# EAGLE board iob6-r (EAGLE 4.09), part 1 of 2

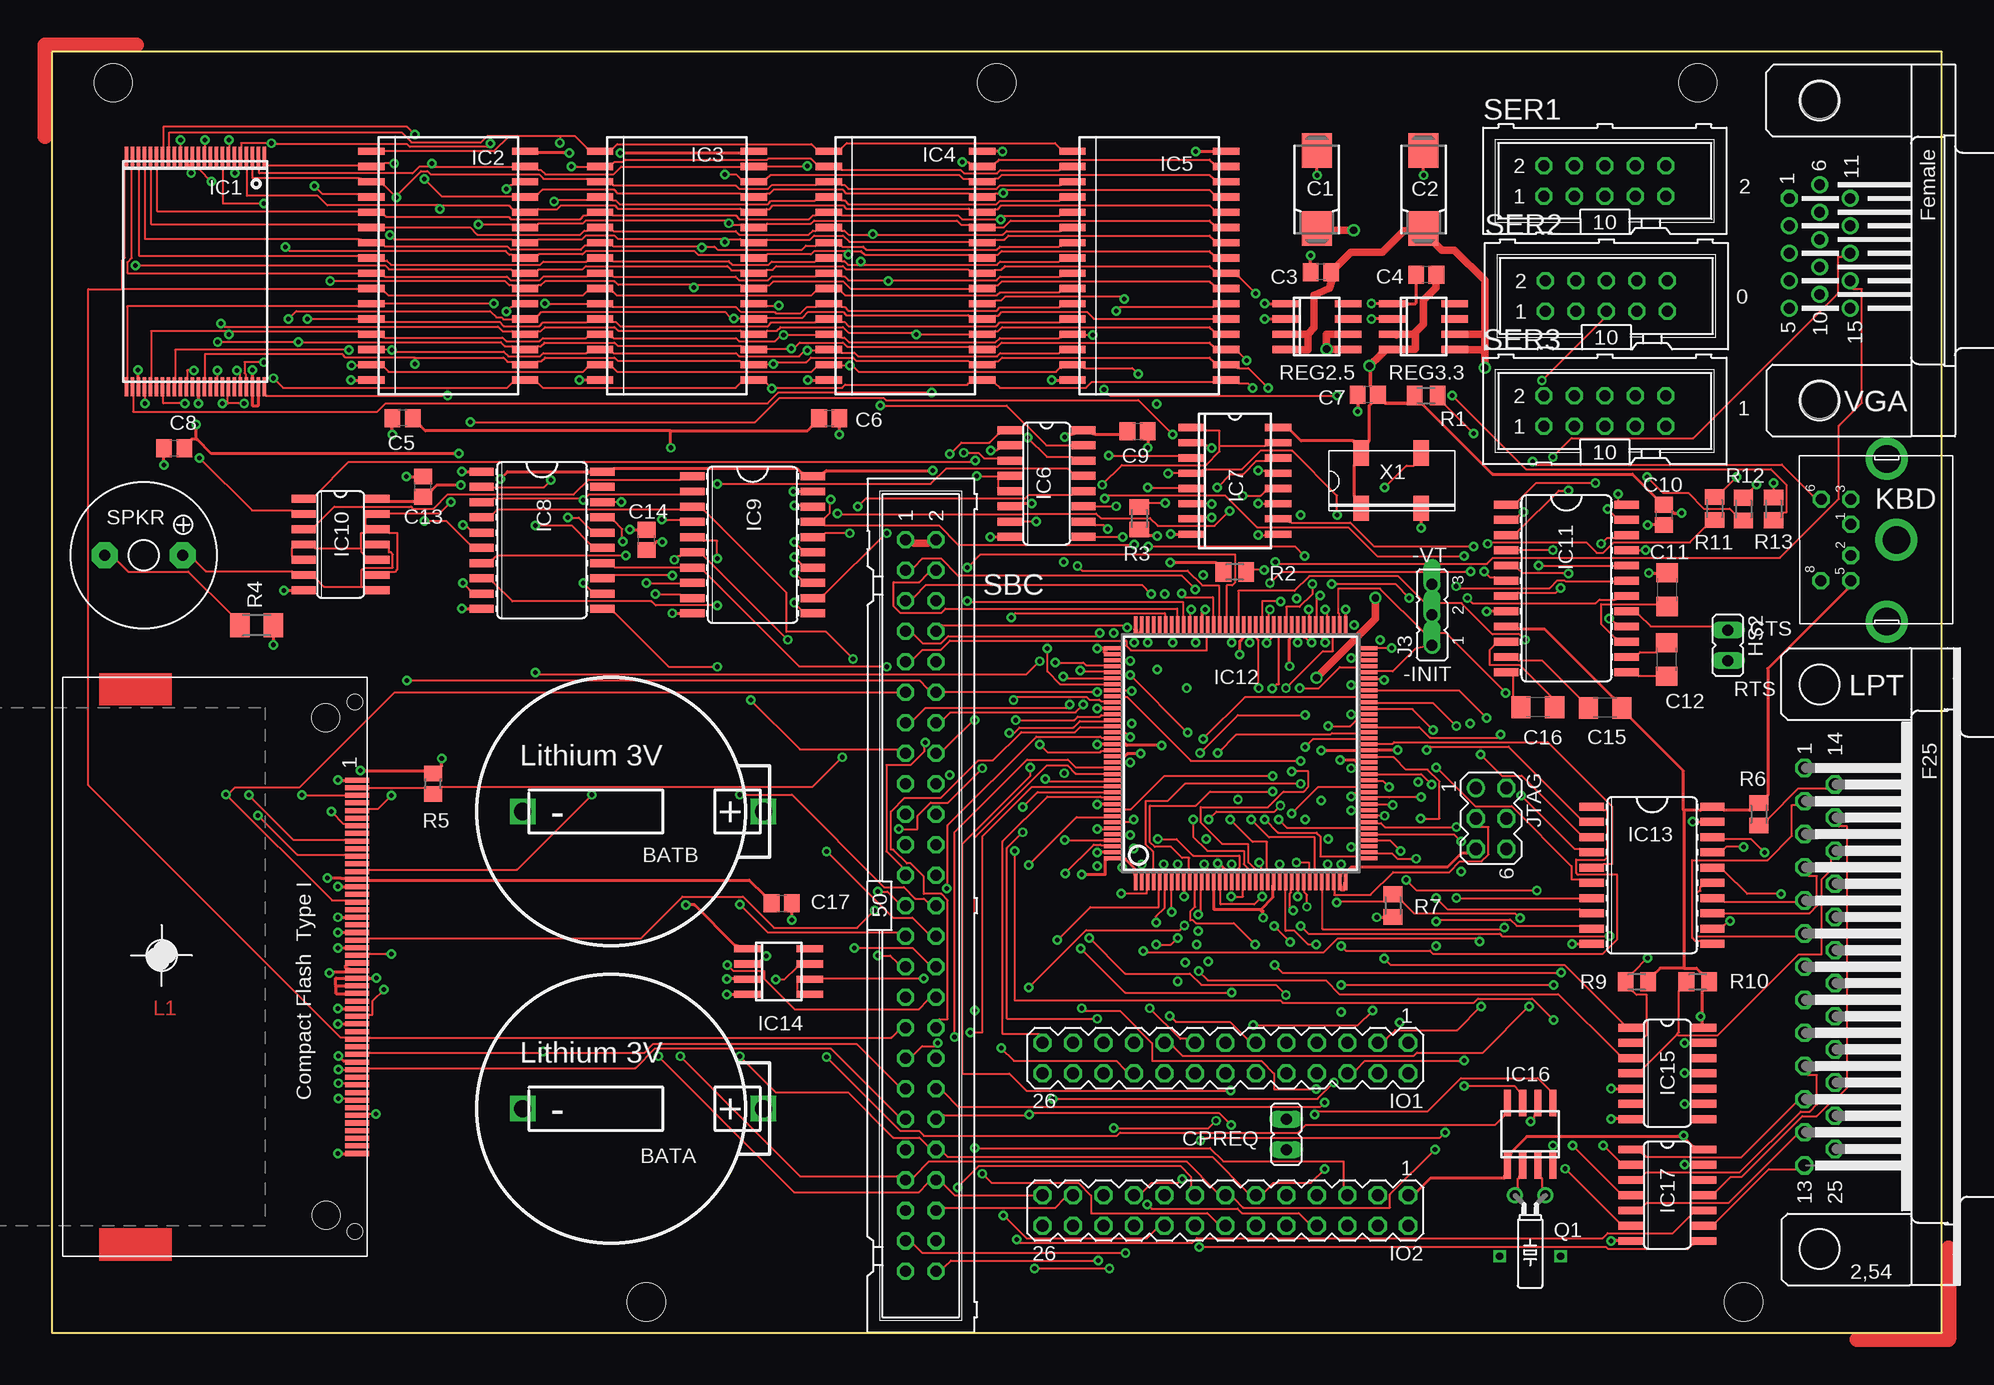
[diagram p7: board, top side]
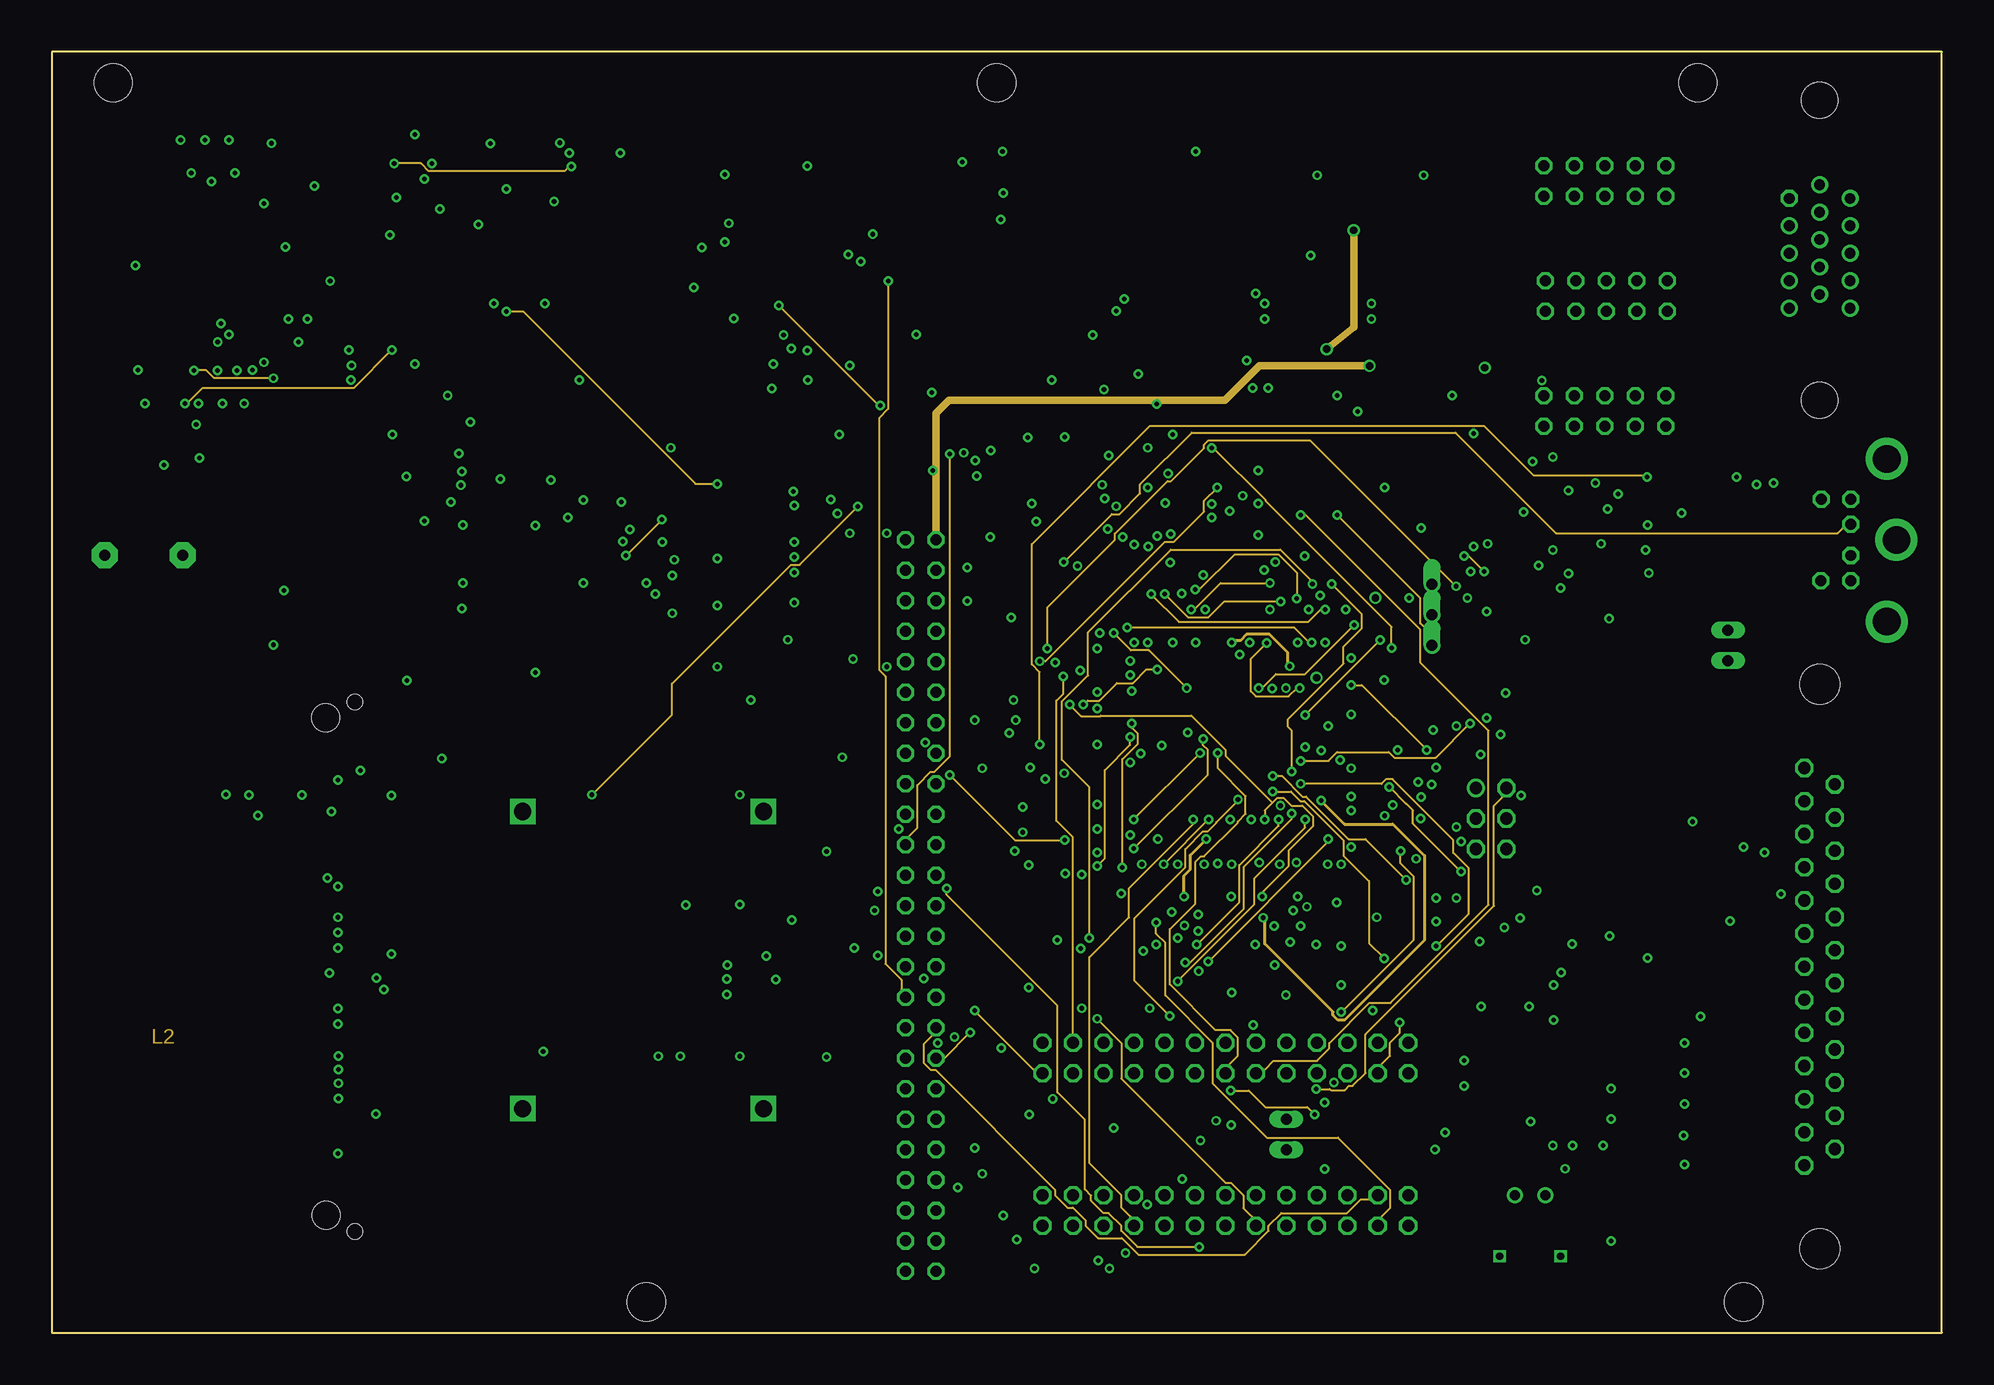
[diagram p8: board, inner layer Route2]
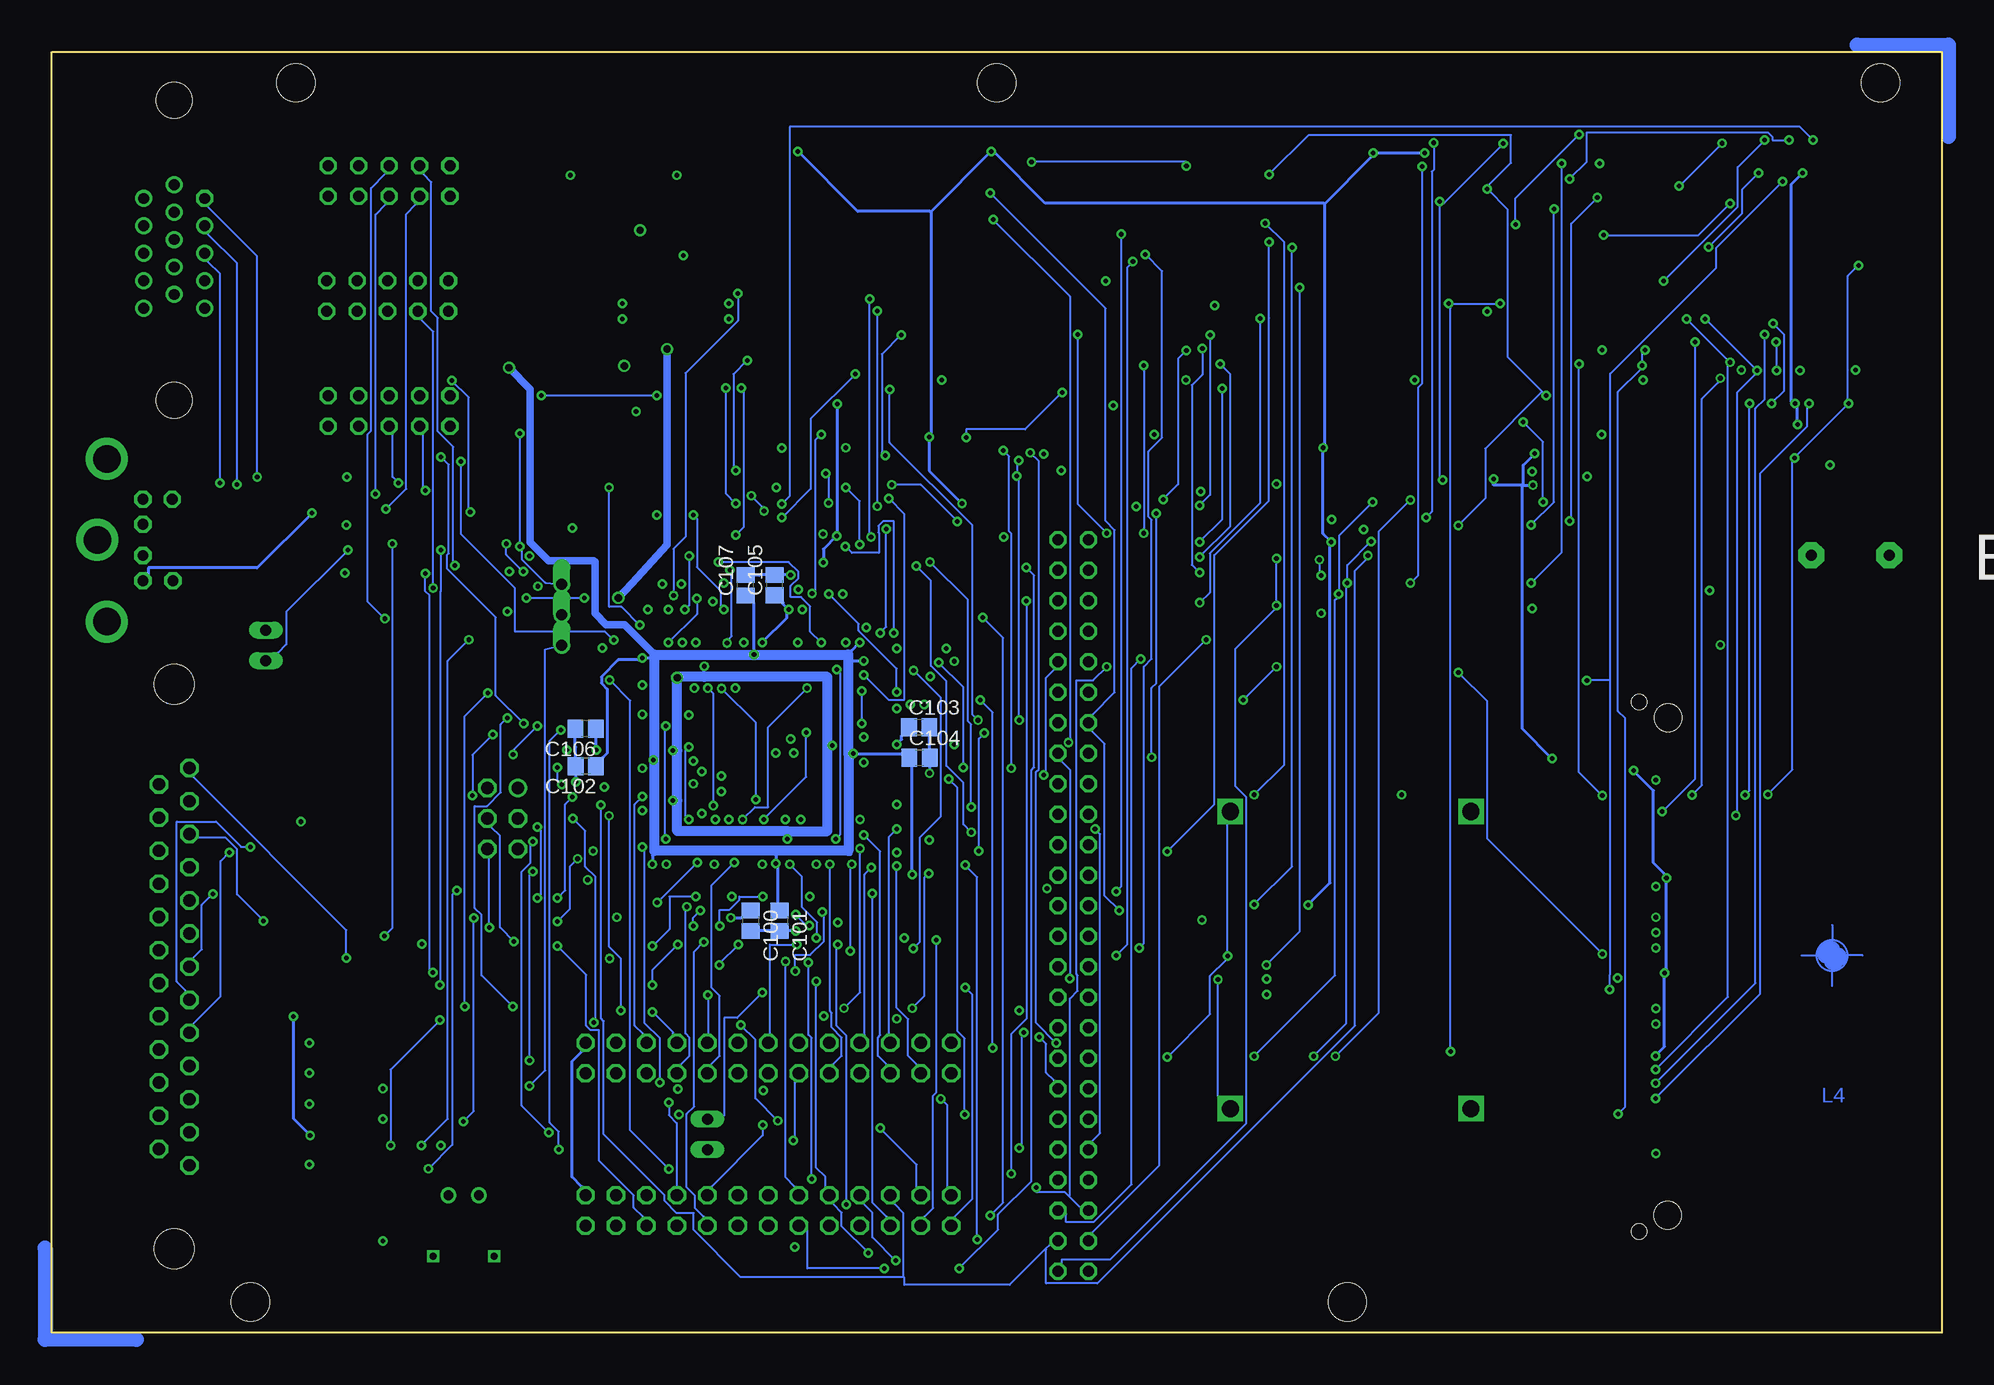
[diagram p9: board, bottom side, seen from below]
Size 157.53 x 106.73 mm. Coordinates in mm from the lower left corner, seen from the top.
Outline: 0,0 157.53,0 157.53,106.73 0,106.73 0,0
Copper layers used: Top, Route2, Bottom
Net classes: 1 power: width 0.254 mm, drill 0.203 mm, clearance 0.381 mm; 2 gnd: width 0.254 mm, clearance 0.381 mm; 3 power2: width 0.254 mm, clearance 0.381 mm
Holes 3.17 mm at 78.77,104.17 141,2.57 5.11,104.17 49.56,2.57 137.19,104.17

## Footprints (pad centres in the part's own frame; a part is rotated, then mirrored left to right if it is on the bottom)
CR2032HOLDER = drill 1.422 square: + 12.7,0; - -7.366,0
085CS_1AR = smd 2.9 x 2.5: + 3.25,0; - -3.25,0
C0805 = smd 1.3 x 1.5: 1 -0.85,0; 2 0.85,0
C1206 = smd 1.6 x 1.8: 1 -1.4,0; 2 1.4,0
CF_SOCKET2_SMT = smd 0.42 x 2: 1 15.545,-17.805; 2 14.275,-17.805; 3 13.005,-17.805; 4 11.735,-17.805; 5 10.465,-17.805; 6 9.195,-17.805; 7 7.925,-17.805; 8 6.655,-17.805; 9 5.385,-17.805; 10 4.115,-17.805; 11 2.845,-17.805; 12 1.575,-17.805; 13 0.305,-17.805; 14 -0.965,-17.805; 15 -2.235,-17.805; 16 -3.505,-17.805; 17 -4.775,-17.805; 18 -6.045,-17.805; 19 -7.315,-17.805; 20 -8.585,-17.805; 21 -9.855,-17.805; 22 -11.125,-17.805; 23 -12.395,-17.805; 24 -13.665,-17.805; 25 -14.935,-17.805; 26 14.91,-17.805; 27 13.64,-17.805; 28 12.37,-17.805; 29 11.1,-17.805; 30 9.83,-17.805; 31 8.56,-17.805; 32 7.29,-17.805; 33 6.02,-17.805; 34 4.75,-17.805; 35 3.48,-17.805; 36 2.21,-17.805; 37 0.94,-17.805; 38 -0.33,-17.805; 39 -1.6,-17.805; 40 -2.87,-17.805; 41 -4.14,-17.805; 42 -5.41,-17.805; 43 -6.68,-17.805; 44 -7.95,-17.805; 45 -9.22,-17.805; 46 -10.49,-17.805; 47 -11.76,-17.805; 48 -13.03,-17.805; 49 -14.3,-17.805; 50 -15.57,-17.805 | hole 2.3: 20.747,-15.177; -20.72,-15.208 | hole 1.27: -22.062,-17.6; 22.048,-17.6
JP1 = drill 0.914 long: 1 0,-1.27; 2 0,1.27
TSOP48 = smd 0.3 x 1.6: 1 -6.25,-9.1; 2 -5.75,-9.1; 3 -5.25,-9.1; 4 -4.75,-9.1; 5 -4.25,-9.1; 6 -3.75,-9.1; 7 -3.25,-9.1; 8 -2.75,-9.1; 9 -2.25,-9.1; 10 -1.75,-9.1; 11 -1.25,-9.1; 12 -0.75,-9.1; 13 -0.25,-9.1; 14 0.25,-9.1; 15 0.75,-9.1; 16 1.25,-9.1; 17 1.75,-9.1; 18 2.25,-9.1; 19 2.75,-9.1; 20 3.25,-9.1; 21 3.75,-9.1; 22 4.25,-9.1; 23 4.75,-9.1; 24 5.25,-9.1; 25 5.25,10.1; 26 4.75,10.1; 27 4.25,10.1; 28 3.75,10.1; 29 3.25,10.1; 30 2.75,10.1; 31 2.25,10.1; 32 1.75,10.1; 33 1.25,10.1; 34 0.75,10.1; 35 0.25,10.1; 36 -0.25,10.1; 37 -0.75,10.1; 38 -1.25,10.1; 39 -1.75,10.1; 40 -2.25,10.1; 41 -2.75,10.1; 42 -3.25,10.1; 43 -3.75,10.1; 44 -4.25,10.1; 45 -4.75,10.1; 46 -5.25,10.1; 47 -5.75,10.1; 48 -6.25,10.1
SOP32 = smd 0.6 x 2.2: 1 -9.525,-6.4; 2 -8.255,-6.4; 3 -6.985,-6.4; 4 -5.715,-6.4; 5 -4.445,-6.4; 6 -3.175,-6.4; 7 -1.905,-6.4; 8 -0.635,-6.4; 9 0.635,-6.4; 10 1.905,-6.4; 11 3.175,-6.4; 12 4.445,-6.4; 13 5.715,-6.4; 14 6.985,-6.4; 15 8.255,-6.4; 16 9.525,-6.4; 17 9.525,6.4; 18 8.255,6.4; 19 6.985,6.4; 20 5.715,6.4; 21 4.445,6.4; 22 3.175,6.4; 23 1.905,6.4; 24 0.635,6.4; 25 -0.635,6.4; 26 -1.905,6.4; 27 -3.175,6.4; 28 -4.445,6.4; 29 -5.715,6.4; 30 -6.985,6.4; 31 -8.255,6.4; 32 -9.525,6.4
SO16 = smd 0.66 x 2.032: 1 -4.445,-3.073; 2 -3.175,-3.073; 3 -1.905,-3.073; 4 -0.635,-3.073; 5 0.635,-3.073; 6 1.905,-3.073; 7 3.175,-3.073; 8 4.445,-3.073; 9 4.445,3.073; 10 3.175,3.073; 11 1.905,3.073; 12 0.635,3.073; 13 -0.635,3.073; 14 -1.905,3.073; 15 -3.175,3.073; 16 -4.445,3.073
SOP16 = smd 0.6 x 2.2: 1 -4.445,-3.6; 2 -3.175,-3.6; 3 -1.905,-3.6; 4 -0.635,-3.6; 5 0.635,-3.6; 6 1.905,-3.6; 7 3.175,-3.6; 8 4.445,-3.6; 9 4.445,3.6; 10 3.175,3.6; 11 1.905,3.6; 12 0.635,3.6; 13 -0.635,3.6; 14 -1.905,3.6; 15 -3.175,3.6; 16 -4.445,3.6
SO20W = smd 0.66 x 2.032: 1 -5.715,-5.029; 2 -4.445,-5.029; 3 -3.175,-5.029; 4 -1.905,-5.029; 5 -0.635,-5.029; 6 0.635,-5.029; 7 1.905,-5.029; 8 3.175,-5.029; 9 4.445,-5.029; 10 5.715,-5.029; 11 5.715,5.029; 12 4.445,5.029; 13 3.175,5.029; 14 1.905,5.029; 15 0.635,5.029; 16 -0.635,5.029; 17 -1.905,5.029; 18 -3.175,5.029; 19 -4.445,5.029; 20 -5.715,5.029
SO14 = smd 0.66 x 2.032: 1 -3.81,-3.073; 2 -2.54,-3.073; 3 -1.27,-3.073; 4 0,-3.073; 5 1.27,-3.073; 6 2.54,-3.073; 7 3.81,-3.073; 8 3.81,3.073; 9 2.54,3.073; 10 1.27,3.073; 11 0,3.073; 12 -1.27,3.073; 13 -2.54,3.073; 14 -3.81,3.073
SO24L = smd 0.66 x 2.032: 1 -6.985,-5.029; 2 -5.715,-5.029; 3 -4.445,-5.029; 4 -3.175,-5.029; 5 -1.905,-5.029; 6 -0.635,-5.029; 7 0.635,-5.029; 8 1.905,-5.029; 9 3.175,-5.029; 10 4.445,-5.029; 11 5.715,-5.029; 12 6.985,-5.029; 13 6.985,5.029; 14 5.715,5.029; 15 4.445,5.029; 16 3.175,5.029; 17 1.905,5.029; 18 0.635,5.029; 19 -0.635,5.029; 20 -1.905,5.029; 21 -3.175,5.029; 22 -4.445,5.029; 23 -5.715,5.029; 24 -6.985,5.029
TQFP144 = smd 0.3 x 1.6: 1 -8.75,-10.6; 2 -8.25,-10.6; 3 -7.75,-10.6; 4 -7.25,-10.6; 5 -6.75,-10.6; 6 -6.25,-10.6; 7 -5.75,-10.6; 8 -5.25,-10.6; 9 -4.75,-10.6; 10 -4.25,-10.6; 11 -3.75,-10.6; 12 -3.25,-10.6; 13 -2.75,-10.6; 14 -2.25,-10.6; 15 -1.75,-10.6; 16 -1.25,-10.6; 17 -0.75,-10.6; 18 -0.25,-10.6; 19 0.25,-10.6; 20 0.75,-10.6; 21 1.25,-10.6; 22 1.75,-10.6; 23 2.25,-10.6; 24 2.75,-10.6; 25 3.25,-10.6; 26 3.75,-10.6; 27 4.25,-10.6; 28 4.75,-10.6; 29 5.25,-10.6; 30 5.75,-10.6; 31 6.25,-10.6; 32 6.75,-10.6; 33 7.25,-10.6; 34 7.75,-10.6; 35 8.25,-10.6; 36 8.75,-10.6; 73 8.75,10.6; 74 8.25,10.6; 75 7.75,10.6; 76 7.25,10.6; 77 6.75,10.6; 78 6.25,10.6; 79 5.75,10.6; 80 5.25,10.6; 81 4.75,10.6; 82 4.25,10.6; 83 3.75,10.6; 84 3.25,10.6; 85 2.75,10.6; 86 2.25,10.6; 87 1.75,10.6; 88 1.25,10.6; 89 0.75,10.6; 90 0.25,10.6; 91 -0.25,10.6; 92 -0.75,10.6; 93 -1.25,10.6; 94 -1.75,10.6; 95 -2.25,10.6; 96 -2.75,10.6; 97 -3.25,10.6; 98 -3.75,10.6; 99 -4.25,10.6; 100 -4.75,10.6; 101 -5.25,10.6; 102 -5.75,10.6; 103 -6.25,10.6; 104 -6.75,10.6; 105 -7.25,10.6; 106 -7.75,10.6; 107 -8.25,10.6; 108 -8.75,10.6 | smd 1.6 x 0.3: 37 10.6,-8.75; 38 10.6,-8.25; 39 10.6,-7.75; 40 10.6,-7.25; 41 10.6,-6.75; 42 10.6,-6.25; 43 10.6,-5.75; 44 10.6,-5.25; 45 10.6,-4.75; 46 10.6,-4.25; 47 10.6,-3.75; 48 10.6,-3.25; 49 10.6,-2.75; 50 10.6,-2.25; 51 10.6,-1.75; 52 10.6,-1.25; 53 10.6,-0.75; 54 10.6,-0.25; 55 10.6,0.25; 56 10.6,0.75; 57 10.6,1.25; 58 10.6,1.75; 59 10.6,2.25; 60 10.6,2.75; 61 10.6,3.25; 62 10.6,3.75; 63 10.6,4.25; 64 10.6,4.75; 65 10.6,5.25; 66 10.6,5.75; 67 10.6,6.25; 68 10.6,6.75; 69 10.6,7.25; 70 10.6,7.75; 71 10.6,8.25; 72 10.6,8.75; 109 -10.6,8.75; 110 -10.6,8.25; 111 -10.6,7.75; 112 -10.6,7.25; 113 -10.6,6.75; 114 -10.6,6.25; 115 -10.6,5.75; 116 -10.6,5.25; 117 -10.6,4.75; 118 -10.6,4.25; 119 -10.6,3.75; 120 -10.6,3.25; 121 -10.6,2.75; 122 -10.6,2.25; 123 -10.6,1.75; 124 -10.6,1.25; 125 -10.6,0.75; 126 -10.6,0.25; 127 -10.6,-0.25; 128 -10.6,-0.75; 129 -10.6,-1.25; 130 -10.6,-1.75; 131 -10.6,-2.25; 132 -10.6,-2.75; 133 -10.6,-3.25; 134 -10.6,-3.75; 135 -10.6,-4.25; 136 -10.6,-4.75; 137 -10.6,-5.25; 138 -10.6,-5.75; 139 -10.6,-6.25; 140 -10.6,-6.75; 141 -10.6,-7.25; 142 -10.6,-7.75; 143 -10.6,-8.25; 144 -10.6,-8.75
SO08 = smd 0.6 x 2.2: 1 -1.905,-2.6; 2 -0.635,-2.6; 3 0.635,-2.6; 4 1.905,-2.6; 5 1.905,2.6; 6 0.635,2.6; 7 -0.635,2.6; 8 -1.905,2.6
MA13-2 = drill 1.016 octagon: 1 -15.24,-1.27; 2 -15.24,1.27; 3 -12.7,-1.27; 4 -12.7,1.27; 5 -10.16,-1.27; 6 -10.16,1.27; 7 -7.62,-1.27; 8 -7.62,1.27; 9 -5.08,-1.27; 10 -5.08,1.27; 11 -2.54,-1.27; 12 -2.54,1.27; 13 0,-1.27; 14 0,1.27; 15 2.54,-1.27; 16 2.54,1.27; 17 5.08,-1.27; 18 5.08,1.27; 19 7.62,-1.27; 20 7.62,1.27; 21 10.16,-1.27; 22 10.16,1.27; 23 12.7,-1.27; 24 12.7,1.27; 25 15.24,-1.27; 26 15.24,1.27
JP2 = drill 0.914 offset: 1 -2.54,0; 2 0,0; 3 2.54,0
MA03-2 = drill 1.016 round: 1 -2.54,-1.27 | drill 1.016 octagon: 2 -2.54,1.27; 3 0,-1.27; 4 0,1.27; 5 2.54,-1.27; 6 2.54,1.27
M_DIN6 = drill 0.9 pad 1.422 octagon: 1 -1.3,-3.75; 2 1.3,-3.75; 3 -3.4,-3.75; 5 3.4,-3.75; 6 -3.4,-6.2; 8 3.4,-6.25 | drill 2.3 pad 3.5 round: SH1 6.8,-0.75; SH2 0,0.05; SH3 -6.75,-0.75
F25H = drill 1.016 octagon: 1 -16.561,-1.27; 2 -13.792,-1.27; 3 -11.049,-1.27; 4 -8.28,-1.27; 5 -5.512,-1.27; 6 -2.769,-1.27; 7 0,-1.27; 8 2.769,-1.27; 9 5.512,-1.27; 10 8.28,-1.27; 11 11.049,-1.27; 12 13.792,-1.27; 13 16.561,-1.27; 14 -15.189,1.27; 15 -12.421,1.27; 16 -9.652,1.27; 17 -6.909,1.27; 18 -4.14,1.27; 19 -1.372,1.27; 20 1.372,1.27; 21 4.14,1.27; 22 6.909,1.27; 23 9.652,1.27; 24 12.421,1.27; 25 15.189,1.27 | hole 3.302: -23.52,0; 23.52,0
TC26H = drill 0.813 round: 1 -1.27,0; 2 1.27,0
M0805 = smd 1.3 x 1.6: 1 -0.95,0; 2 0.95,0
M1206 = smd 1.6 x 2: 1 -1.4,0; 2 1.4,0
R0805 = smd 1.3 x 1.5: 1 -0.85,0; 2 0.85,0
ML50 = drill 0.914 octagon: 1 -30.48,-1.27; 2 -30.48,1.27; 3 -27.94,-1.27; 4 -27.94,1.27; 5 -25.4,-1.27; 6 -25.4,1.27; 7 -22.86,-1.27; 8 -22.86,1.27; 9 -20.32,-1.27; 10 -20.32,1.27; 11 -17.78,-1.27; 12 -17.78,1.27; 13 -15.24,-1.27; 14 -15.24,1.27; 15 -12.7,-1.27; 16 -12.7,1.27; 17 -10.16,-1.27; 18 -10.16,1.27; 19 -7.62,-1.27; 20 -7.62,1.27; 21 -5.08,-1.27; 22 -5.08,1.27; 23 -2.54,-1.27; 24 -2.54,1.27; 25 0,-1.27; 26 0,1.27; 27 2.54,-1.27; 28 2.54,1.27; 29 5.08,-1.27; 30 5.08,1.27; 31 7.62,-1.27; 32 7.62,1.27; 33 10.16,-1.27; 34 10.16,1.27; 35 12.7,-1.27; 36 12.7,1.27; 37 15.24,-1.27; 38 15.24,1.27; 39 17.78,-1.27; 40 17.78,1.27; 41 20.32,-1.27; 42 20.32,1.27; 43 22.86,-1.27; 44 22.86,1.27; 45 25.4,-1.27; 46 25.4,1.27; 47 27.94,-1.27; 48 27.94,1.27; 49 30.48,-1.27; 50 30.48,1.27
ML10 = drill 0.914 octagon: 1 -5.08,-1.27; 2 -5.08,1.27; 3 -2.54,-1.27; 4 -2.54,1.27; 5 0,-1.27; 6 0,1.27; 7 2.54,-1.27; 8 2.54,1.27; 9 5.08,-1.27; 10 5.08,1.27
KSS1201 = drill 0.914 pad 2.159 octagon: + 3.251,0; - -3.251,0
HDF15H = drill 0.9 octagon: 1 4.329,2.54 | drill 0.9 round: 2 2.043,2.54; 3 -0.243,2.54; 4 -2.529,2.54; 5 -4.815,2.54; 6 5.472,0; 7 3.186,0; 8 0.9,0; 9 -1.386,0; 10 -3.672,0; 11 4.329,-2.54; 12 2.043,-2.54; 13 -0.243,-2.54; 14 -2.529,-2.54; 15 -4.815,-2.54 | hole 3: -12.5,0; 12.5,0
SG636 = smd 1.3 x 2.1: P$1 0,0; P$2 5,0; P$3 5,4.6; P$4 0,4.6

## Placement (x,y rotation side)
BATA  [CR2032HOLDER]  46.61,18.67 0 top
BATB  [CR2032HOLDER]  46.61,43.43 0 top
C1  10u  [085CS_1AR]  105.44,95.28 270 top
C2  10u  [085CS_1AR]  114.33,95.28 270 top
C3  0u1  [C0805]  105.77,88.39 180 top
C4  0u1  [C0805]  114.55,88.16 180 top
C5  0u1  [C0805]  29.24,76.23 180 top
C6  0u1  [C0805]  64.8,76.23 0 top
C7  0u1  [C0805]  109.68,78.16 180 top
C8  0u1  [C0805]  10.19,73.69 180 top
C9  0u1  [C0805]  90.5,75.13 0 top
C10  0u1  [C0805]  134.37,68.15 270 top
C11  [C1206]  134.65,61.93 90 top
C12  [C1206]  134.59,56.11 90 top
C13  0u1  [C0805]  30.94,70.51 90 top
C14  0u1  [C0805]  49.56,66.07 90 top
C15  [C1206]  129.46,52.07 180 top
C16  [C1206]  123.85,52.12 180 top
C17  0u1  [C0805]  60.83,35.79 0 top
C100  0u1  [C0805]  99.29,34.34 270 bottom
C101  0u1  [C0805]  96.88,34.34 270 bottom
C102  0u1  [C0805]  113.03,47.22 180 bottom
C103  0u1  [C0805]  85.24,50.47 0 bottom
C104  0u1  [C0805]  85.22,47.93 0 bottom
C105  0u1  [C0805]  97.28,62.31 90 bottom
C106  0u1  [C0805]  113.06,50.32 180 bottom
C107  0u1  [C0805]  99.72,62.28 90 bottom
CF1  CF_CMM_SOCKET2  [CF_SOCKET2_SMT]  7.65,30.51 90 top
CPREQ  [JP1]  102.9,16.54 0 top
HS2  [JP1]  139.7,57.28 180 top
IC1  LH28F400BVHE-BL  [TSOP48]  11.46,88.93 180 top
IC2  TC554001AF  [SOP32]  33.05,88.93 270 top
IC3  TC554001AF  [SOP32]  52.1,88.93 270 top
IC4  TC554001AF  [SOP32]  71.15,88.93 270 top
IC5  TC554001AF  [SOP32]  91.47,88.93 270 top
IC6  74ACT138D  [SO16]  82.91,70.76 270 top
IC7  74HC367E  [SOP16]  98.6,70.99 270 top
IC8  74ACT373D  [SO20W]  40.84,66.04 270 top
IC9  74ACT245DW  [SO20W]  58.39,65.66 270 top
IC10  74ACT32D  [SO14]  24.05,65.68 270 top
IC11  MAX208ECWG  [SO24L]  126.24,62.03 270 top
IC12  [TQFP144]  99.09,48.29 0 top
IC13  74ACT245DW  [SO20W]  133.38,38.13 270 top
IC14  [SO08]  60.58,30.1 270 top
IC15  74ACT05D  [SO14]  134.65,21.62 270 top
IC16  DS1302  [SO08]  123.22,16.54 0 top
IC17  74ACT04D  [SO14]  134.65,11.46 270 top
IO1  [MA13-2]  97.82,22.89 180 top
IO2  [MA13-2]  97.82,10.19 180 top
J3  [JP2]  115.04,59.82 90 top
JTAG  [MA03-2]  119.96,42.85 270 top
KBD  [M_DIN6]  153.7,66.07 270 top
LPT  [F25H]  147.35,30.51 270 top
Q1  32768  [TC26H]  123.22,11.46 180 top
R1  10K  [M0805]  114.55,78.11 180 top
R2  10K  [M0805]  98.6,63.4 0 top
R3  10K  [M0805]  90.63,67.87 90 top
R4  100  [M1206]  17.07,58.95 0 top
R5  10K  [R0805]  31.78,45.75 90 top
R6  4K7  [M0805]  142.27,43.21 90 top
R7  10K  [M0805]  111.79,35.59 90 top
R9  4K7  [M0805]  132.11,29.24 0 top
R10  4K7  [M0805]  137.19,29.24 0 top
R11  68  [M0805]  138.58,68.68 90 top
R12  68  [M0805]  141,68.63 90 top
R13  68  [M0805]  143.51,68.66 90 top
REG2.5  TPS77725D  [SO08]  105.44,83.85 270 top
REG3.3  TPS77733D  [SO08]  114.33,83.85 270 top
SBC  ML50E  [ML50]  72.42,35.59 270 top
SER1  [ML10]  129.44,95.99 0 top
SER2  [ML10]  129.57,86.39 0 top
SER3  [ML10]  129.44,76.81 0 top
SPKR  KSS1201  [KSS1201]  7.65,64.8 0 top
U$34  [PASS-ROUND]  9.14,31.45 0 top
U$42  [ANGLE-ARROW-NW1-16]  0.08,106.65 0 top
U$43  [ANGLE-ARROW-SE1-16]  157.45,0.08 0 top
VGA  [HDF15H]  147.35,90.2 90 top
X1  29.4912MHz  [SG636]  109.14,68.71 0 top

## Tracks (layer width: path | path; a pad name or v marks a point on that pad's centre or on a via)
2V5  (via drill 0.38, 0.61)
  Top 0.254: 100.76,35.27 96.88,35.27 96.88,36.91 IC12.14 | 100.76,35.27 101.79,36.3 101.79,36.91 IC12.24 | v100.95,34.58 100.95,35.15 100.8,35.15 100.76,35.27 | v96.11,60.26 95.85,60.26 95.85,59.65 IC12.97 | v98.32,57.52 98.32,58.09 IC12.92 | v112.15,48.56 110.48,48.56 IC12.55 108.92,48.53 v105.79,48.53 | v87.12,49.02 87.69,49.02 IC12.125 89.26,49.02 89.52,49.02 89.6,48.95 v92.49,48.95 | v94.36,36.33 94.36,36.91 IC12.9 | v103.16,55.54 103.16,57.79 103.31,57.94 103.31,58.09 IC12.82
  Top 0.61: v106.25,81.97 106.22,81.94 | v110.31,61.24 110.31,59.49 v105.41,54.58 | 106.22,81.94 REG2.5.5 | 106.22,81.94 106.22,83.21 REG2.5.6 | C1.+ 105.59,91.87 v108.51,91.87
  Route2 0.254: v94.36,36.33 94.36,38.09 94.89,38.62 94.89,39.8 v96.23,41.14 | v98.32,57.52 98.67,57.67 99.05,57.67 99.58,58.2 101.49,58.2 103.01,56.68 103.01,55.88 v103.16,55.54 | v105.79,44.34 107.73,42.39 111.77,42.39 114.4,39.76 114.4,32.72 107.73,26.05 107.2,26.05 106.78,26.47 106.78,26.73 101.1,32.41 101.1,34.24 v100.95,34.58
  Route2 0.61: v108.51,91.87 108.51,83.77 106.22,81.94 v106.25,81.97
  Bottom 0.254: v100.95,34.58 100.04,34.58 C100.1 | C105.1 96.57,60.83 96.57,60.72 v96.11,60.26 96.27,59.92 96.27,59.58 v98.32,57.52 | v112.15,48.56 112.15,49.59 C106.1 | v87.12,49.02 86.7,49.44 86.7,49.75 C103.1 | v96.23,41.14 96.23,41.81 | 103.16,54.66 v103.16,55.54 | 92.89,48.95 v92.49,48.95 | 105.41,48.53 v105.79,48.53 | 105.41,44.34 v105.79,44.34
  Bottom 0.61: v106.25,81.97 106.25,65.66 108.74,62.92 109.19,62.41 v110.31,61.24
  Bottom 0.813: v105.41,54.58 105.41,48.53 105.41,44.34 105.41,41.81 96.23,41.81 92.89,41.81 92.89,48.95 92.89,54.66 103.16,54.66 105.54,54.66
5V  (via drill 0.38, 0.61)
  Top 0.254: v23.88,23.08 24.33,22.62 24.49,22.62 CF1.44 | v23.11,29.97 23.23,30.09 24.49,30.09 CF1.38 24.49,30.35 24.49,30.62 CF1.13 | v22.96,37.9 24.1,37.9 24.14,37.86 24.49,37.86 CF1.32 26.43,37.71 58.13,37.71 59.35,36.49 C17.1 | v25.7,46.85 31.04,46.85 R5.2 32.49,47.23 v32.49,47.84 | 11.57,97.26 11.34,97.26 IC1.14 | 11.57,97.26 IC1.13 | v12.22,77.44 12.22,78.05 IC1.37 | 12.03,74.43 v12.03,75.69 | 12.03,74.43 11.65,74.43 C8.1 | v11.61,96.65 11.61,97.14 11.57,97.26 | IC10.14 28.11,69.25 30.2,69.25 C13.1 31.69,70.24 32.07,70.62 v34.09,70.62 | v37.36,71.16 37.97,71.77 44.87,71.77 IC8.20 46.85,72.03 62.09,72.03 62.43,71.69 IC9.20 64.41,71.69 64.57,71.84 v73.41,71.84 | v33.93,73.25 13.28,73.25 12.14,74.4 12.03,74.43 | IC7.16 103.28,75.16 104.11,74.32 108.5,74.32 X1.P$4 | X1.P$1 108.53,69.75 108.53,72.26 X1.P$4 | v92.11,66.4 91.39,66.4 R3.1 | v93.22,64.19 97.03,64.19 R2.1 | 109.91,78.89 C7.1 | v109.83,80.57 109.91,80.11 | REG3.3.4 110.63,81.67 110.79,81.51 | REG3.3.3 112.08,82.93 112.19,83.21 | X1.P$4 109.79,74.32 109.79,77.25 109.94,77.41 C7.1 | 112.99,77.44 R1.2 114.25,77.37 120.08,71.54 131.74,71.54 133.64,69.63 C10.1 135.09,68.38 135.17,68.3 v135.85,68.3 | C7.1 111.16,77.44 | 135.97,16.33 136.73,15.57 IC17.14 | 135.97,16.33 122.94,16.33 121.6,15 IC16.1 121.03,12.87 114.9,12.87 113.79,11.76 IO2.1 | IC11.9 122.21,58.62 124.42,58.62 130.1,52.95 C15.1 131.62,51.19 136,46.81 136,43.65 136.04,43.54 | 137.53,26.35 137.53,28.45 R10.2 137.49,29.97 137.07,30.39 136.04,30.39 | 137.53,26.35 137.53,25.74 IC15.14 | 136.04,30.39 134.06,30.39 133.68,30.01 R9.2 | KBD.5 149.64,61.98 143.01,55.35 143.01,44.79 R6.2 141.49,43.54 139.4,43.54 IC13.20 137.41,43.54 136.04,43.54
  Top 0.254: 136.04,43.54 136.04,30.39 | v136,16.45 135.97,16.33 | 137.53,26.35 v137.41,26.35
  Top 0.305: 109.91,80.11 109.91,78.89 | 111.16,77.44 112.99,77.44
  Top 0.61: v109.83,80.57 110.79,81.51 111.23,81.94 REG3.3.4 113.59,81.94 113.64,81.99 113.64,83.21 | 113.64,83.21 112.19,83.21 | C4.1 115.34,88.1 115.34,87.07 114.33,86.06 114.33,84.05 113.51,83.24 113.51,83.19 113.61,83.19 113.64,83.21 | SBC.1 71.84,65.79 72.99,65.79 SBC.2
  Route2 0.254: 92.08,77.7 v92.08,77.41 | v73.41,71.84 73.69,71.84
  Route2 0.61: SBC.2 73.69,71.84 73.69,76.61 74.78,77.7 92.08,77.7 97.79,77.7 100.63,80.57 v109.83,80.57
  Bottom 0.254: v23.88,23.08 23.11,23.84 v23.11,29.97 22.96,30.32 v22.96,37.9 23.11,38.24 24.03,39.15 24.03,45.17 v25.7,46.85 | v12.03,75.69 12.03,77.25 v12.22,77.44 12.56,77.6 12.56,95.69 v11.61,96.65 | 34.96,70.62 37.36,70.62 v37.36,71.16 | 34.96,70.62 34.89,70.62 | 34.89,70.62 v34.09,70.62 | v33.93,73.25 34.89,72.3 34.89,70.62 | v32.49,47.84 34.96,50.32 34.96,70.62 | v93.22,64.19 93.22,65.29 v92.11,66.4 92.08,66.74 v92.08,77.41 | IO1.1 113.37,23.42 114.17,22.62 114.17,12.98 113.37,12.18 IO2.1 | v136,16.45 137.41,17.86 v137.41,26.35 | v135.85,68.3 140.42,63.73 149.49,63.73 149.49,63.2 KBD.5
B0  (via drill 0.38)
  Top 0.178: v80.34,51.04 85.22,51.04 85.52,51.35 87.35,51.35 87.46,51.46 87.69,51.46 IC12.120 | v87.69,78.59 88.19,78.09 v107.12,78.09 | v116.73,78.09 122.86,71.96 143.28,71.96 144.58,70.66 144.58,68.34 144.27,68.34 R13.1
  Bottom 0.178: v80.34,51.04 80.8,51.5 80.8,67.27 87.69,74.17 v87.69,78.59 | v107.12,78.09 v116.73,78.09
C0_L  (via drill 0.38)
  Top 0.178: v104.76,60.26 104.76,59.65 IC12.79 | v104.42,64.72 103.62,65.52 v91.39,65.52 | v87.35,58.32 87.08,58.05 74.7,58.05 74.09,57.44 72.57,57.44 71.84,58.17 SBC.7
  Bottom 0.178: v104.76,60.26 104.42,60.6 v104.42,64.72 | v91.39,65.52 90.86,64.99 88.61,64.99 88.61,66.66 88.65,66.7 88.65,67.23 88.27,67.61 87.35,67.61 v87.35,58.32
C1_L  (via drill 0.38)
  Top 0.178: v104.99,57.52 104.88,57.52 104.5,57.9 104.38,57.9 104.38,58.09 IC12.80 | v89.64,58.78 89.45,58.97 74.17,58.97 SBC.8
  Route2 0.178: v104.99,57.52 104.76,57.52 103.51,58.78 v89.64,58.78
CF_DETECT_L  (via drill 0.38)
  Top 0.178: CF1.26 26.43,45.4 31.04,45.4 R5.1 32.52,45.48 63.39,45.48 v65.86,47.96 | v99.24,69.75 100.76,69.75 101.1,70.09 IC7.12 | v98.17,68.49 96.91,67.23 92.19,67.23 91.54,67.88 87.43,67.88 87.05,68.26 81.03,68.26 80.95,68.19 65.56,68.19 v65.48,68.26
  Bottom 0.178: v99.24,69.75 98.17,68.68 v98.17,68.49 | v65.48,68.26 65.48,54.13 65.86,53.75 v65.86,47.96
CF_L  (via drill 0.38)
  Top 0.178: v45.02,44.83 38.77,38.58 26.43,38.58 CF1.7 | v67.16,68.83 67.84,69.52 81.14,69.52 81.45,69.82 84.99,69.82 IC6.12
  Route2 0.178: v45.02,44.83 51.69,51.5 51.69,54.09 61.6,64 62.32,64 v67.16,68.83
CF_READY  (via drill 0.38)
  Top 0.178: v28.3,31.57 26.43,31.57 CF1.37 | v40.3,55 40.45,54.85 81.22,54.85 v82.32,55.96 | v97.14,70.43 98.25,71.54 99.31,71.54 100.42,72.64 101.1,72.64 IC7.14
  Route2 0.178: v82.32,55.96 82.82,55.96 92.76,65.9 93.52,65.9 96.04,68.41 96.04,69.33 v97.14,70.43
  Bottom 0.178: v28.3,31.57 37.9,41.17 37.9,52.6 v40.3,55
CPUDX0
  Top 0.178: IC12.122 87.69,50.47 85.71,50.47 85.29,50.05 80.8,50.05 78.44,47.69 77.22,47.69 74.09,44.56 71.08,44.56 69.94,43.42 69.94,40.26 70.13,40.26 71.27,39.12 71.58,39.12 72.68,38.01 72.68,36.56 74.13,36.56 74.66,36.03 74.66,26.12 73.98,26.12 SBC.34
  Route2 0.178: IO2.3 109.79,11.11 109.11,11.11 107.96,9.97 102.48,9.97 101.41,8.9 101.41,8.48 99.43,6.5 90.55,6.5 89.18,7.87 87.2,7.87 86.17,8.9 86.17,9.36 85.1,10.43 84.65,10.43 83.62,11.46 83.62,11.91 73.63,21.89 73.25,21.89 72.68,22.47 72.68,24.07 73.37,24.75 SBC.34
CPUDX1  (via drill 0.38)
  Top 0.178: v76.53,25.02 77.56,25.02 77.56,41.36 81.67,45.48 87.69,45.48 IC12.132 | v76.91,15.38 96.53,15.38 97.64,14.27 107.66,14.27 107.66,12.18 IO2.5
  Route2 0.178: v76.53,25.02 74.36,22.85 SBC.36
  Bottom 0.178: v76.91,15.38 76.68,15.61 76.68,24.68 v76.53,25.02
CPUDX2  (via drill 0.38)
  Top 0.178: v75.23,24.64 75.23,41.71 81.29,47.76 84.68,47.76 85.33,47.12 87.69,47.12 IC12.129 | v106.1,19.19 105.75,18.85 75.54,18.85 74.36,20.03 SBC.38
  Bottom 0.178: v75.23,24.64 74.66,24.07 74.66,21.67 74.02,21.02 SBC.38 | v106.1,19.19 106.1,18.12 105.45,17.48 105.45,12.18 IO2.7
CPUDX3  (via drill 0.38)
  Top 0.178: v82.78,46.13 82.93,45.97 87.69,45.97 IC12.131 | SBC.40 74.36,18.12 81.37,18.12 v81.45,18.2 81.79,18.31 97.29,18.31 v98.29,17.32
  Bottom 0.178: v82.78,46.13 82.05,45.4 82.05,25.13 81.45,24.52 v81.45,18.2 | v98.29,17.32 98.29,16.45 102.55,12.18 IO2.9
CPUDX4  (via drill 0.38)
  Top 0.178: v50.28,61.56 50.32,61.52 52.37,61.52 IC9.9 | v47.46,69.22 IC8.18 | v111.05,54.39 110.97,54.47 110.48,54.47 IC12.67 | v106.1,13.63 104.95,12.48 101.83,12.48 101.1,11.76 IO2.11 99.62,11.76 96.72,14.66 74.66,14.66 74.36,14.96 SBC.42 72.99,15.57 72.3,16.26 70.13,16.26 66.36,20.03 60.34,20.03 v57.33,23.04
  Bottom 0.178: v47.46,69.22 50.2,66.47 50.2,61.63 v50.28,61.56 50.43,61.21 50.58,61.06 50.58,29.78 v57.33,23.04 | v111.05,54.39 109.33,52.68 109.33,16.87 v106.1,13.63
CPUDX5  (via drill 0.38)
  Top 0.178: v47.57,65.94 47.54,65.94 47.54,66.97 46.85,67.65 IC8.17 | v49.56,62.47 52.37,62.47 IC9.8 | v115.13,50.24 113.41,51.96 110.48,51.96 IC12.62 | v115.28,15.27 111.54,11.53 111.54,10.43 99.28,10.43 98.55,11.15 IO2.13 97.07,11.76 94.55,14.27 73.1,14.27 71.84,13.02 SBC.43 70.47,13.06 62.36,13.06 v52.37,23.04
  Bottom 0.178: v47.57,65.94 49.56,63.96 v49.56,62.47 49.63,62.13 49.63,25.78 v52.37,23.04 | v115.13,50.24 116.04,49.33 116.04,17.51 115.28,16.75 v115.28,15.27
CPUDX6  (via drill 0.38)
  Top 0.178: IC8.14 46.85,63.84 46.93,63.77 52.37,63.77 IC9.7 54.36,63.46 62.32,55.5 v69.6,55.5 | v106.36,50.55 108.23,50.55 108.65,50.97 108.92,50.97 IC12.60 | v75.5,12.1 77.29,13.89 94.06,13.89 94.93,13.02 94.93,12.18 IO2.15
  Route2 0.178: v106.36,41.14 106.36,40.91 v96.38,30.92
  Bottom 0.178: v106.36,50.55 106.44,50.47 106.44,41.21 v106.36,41.14 | v96.38,30.92 96.38,12.94 95.62,12.18 IO2.15 | 72.74,11.36 73.1,11.72 75.5,11.72 v75.5,12.1 | 72.74,11.36 71.84,10.46 SBC.45 | v69.6,55.5 70.74,54.36 72.15,54.36 72.15,29.9 72.03,29.78 72.03,28.49 72.68,27.84 72.68,11.42 72.74,11.36
CPUDX7  (via drill 0.38)
  Top 0.178: v51.73,63.12 46.85,63.12 IC8.13 | v51.88,64.41 52.18,64.72 52.37,64.72 IC9.6 54.36,64.72 v61.33,57.75 | v104.46,48.79 105.14,49.48 108.92,49.48 IC12.57 | v89.48,6.65 72.53,6.65 71.84,7.34 SBC.47
  Route2 0.178: v104.46,42.77 104.46,42.09 100.23,37.86 100.23,35.69 v93.83,29.29
  Bottom 0.178: v51.73,63.12 51.88,63.27 v51.88,64.41 | v104.46,48.79 104.72,48.53 104.72,43.04 v104.46,42.77 | v93.83,29.29 93.83,13.74 93.07,12.98 93.07,12.18 IO2.17 92.42,10.73 91.69,10.01 91.69,8.86 v89.48,6.65 | v61.33,57.75 65.21,53.86 65.21,13.97 70.85,8.33 SBC.47
CPUDX8  (via drill 0.38)
  Top 0.178: v55.46,60.6 50.32,60.6 49.97,60.95 38.39,60.95 36.79,62.55 IC8.8 | v55.46,64.53 55.46,65.98 54.36,65.98 IC9.5 | v103.35,43.27 105.56,45.48 108.92,45.48 IC12.49 | v94.21,12.83 93.87,12.48 91.66,12.48 90.93,11.76 IO2.19 | v87.2,6.01 74.93,6.01 74.36,5.44 SBC.50
  Route2 0.178: v103.35,43.27 103.35,42.81 99.35,38.81 99.35,35.34 94.86,30.85 v94.48,30.85
  Bottom 0.178: v55.46,64.53 v55.46,60.6 55.61,60.26 58.89,56.98 58.89,45.55 57.98,44.64 57.98,17.44 69.33,6.08 73.37,6.08 73.37,5.78 SBC.50 | v94.48,30.85 94.48,24.83 94.21,24.56 v94.21,12.83 | v87.2,6.01 89.14,7.95 89.14,10.01 89.87,10.73 IO2.19
CPUDX9  (via drill 0.38)
  Top 0.178: v47.84,64.76 37.1,64.76 36.79,64.45 IC8.7 | v50.85,67.77 52.37,67.77 IC9.4 | v111.77,43.99 110.48,43.99 IC12.46
  Route2 0.178: v47.84,64.76 v50.85,67.77
  Bottom 0.178: v111.77,43.99 111.77,26.2 111.54,25.97 111.54,16.52 106.48,11.46 106.48,11 105.45,9.97 104.04,9.97 104.04,8.56 100.11,4.64 86.55,4.64 | 86.55,4.64 86.55,9.97 87.31,10.73 IO2.21 | 74.72,6.98 77.71,3.99 86.47,3.99 86.47,4.6 86.55,4.64 | 74.72,6.98 74.36,7.34 SBC.48 | v47.84,64.76 47.99,64.41 48.91,63.5 48.91,25.59 70.4,4.1 74.66,4.1 74.66,6.92 74.72,6.98
CPUDX10  (via drill 0.38)
  Top 0.178: IC8.4 36.79,68.26 37.1,68.57 52.37,68.57 IC9.3 54.36,68.53 61.21,61.67 61.21,58.39 64.53,58.39 v66.78,56.15 | v111.09,43.08 110.48,43.08 IC12.44 | v110.1,26.85 108.88,25.63 v100.11,25.63 | v97.03,17.67 96.42,17.06 v88.49,17.06 | SBC.46 74.36,10.43 83.65,10.43 84.38,11.15 IO2.23
  Bottom 0.178: v111.09,43.08 111.09,32.14 110.1,31.15 v110.1,26.85 | v100.11,25.63 98.9,24.41 98.9,19.53 v97.03,17.67 | v88.49,17.06 85.45,14.01 85.45,12.18 IO2.23 | v66.78,56.15 67.54,55.38 67.54,12.37 70.7,9.21 72.99,9.21 72.99,9.89 SBC.46
CPUDX11  (via drill 0.38)
  Top 0.178: 44.3,69.48 44.41,69.48 44.79,69.86 52.37,69.86 IC9.2 | 44.3,69.48 36.79,69.48 IC8.3 | v108.31,40.49 108.92,40.49 IC12.39 | v106.86,20.87 105.49,19.49 v83.43,19.49 | IO2.25 75.23,11.46 74.32,12.37 SBC.44 72.99,12.45 72.26,11.72 61.86,11.72 v50.55,23.04 | v44.3,69.41 44.3,69.48
  Bottom 0.178: v108.31,40.49 108.12,40.3 108.12,25.78 106.86,24.52 v106.86,20.87 | v83.43,19.49 82.89,18.96 82.89,12.18 IO2.25 | v44.3,69.41 46.93,66.78 46.93,26.66 v50.55,23.04
CTS2
  Top 0.178: IC11.17 132.27,59.84 133.26,58.85 138.29,58.85 HS2.1
DA0  (via drill 0.38)
  Top 0.178: v21.89,95.54 22.54,94.89 25.55,94.89 IC2.4 | IC1.5 15.76,98.82 15.76,99.12 v18.31,99.12 18.66,99.05 29.59,99.05 29.82,98.82 36.3,98.82 v36.56,99.09 | v41.59,71.04 41.02,70.47 36.79,70.47 IC8.2 | v41.86,94.28 41.97,94.4 44.6,94.4 IC3.4 46.77,94.36 47,94.36 47.31,94.06 59.69,94.06 59.96,94.32 63.58,94.32 63.65,94.4 IC4.4 65.82,94.36 66.05,94.36 66.36,94.06 78.74,94.06 79.01,94.32 83.96,94.32 84,94.36 IC5.4
  Bottom 0.178: v18.31,99.12 v21.89,95.54 | v41.59,71.04 41.86,71.31 v41.86,94.28 41.52,94.13 v36.56,99.09
DA1  (via drill 0.38)
  Top 0.178: 32.33,93.94 38.05,93.94 38.35,93.64 IC2.28 40.53,93.64 42.13,93.64 42.43,93.94 46.89,93.94 47.16,93.68 57.37,93.68 57.4,93.64 IC3.28 59.58,93.64 59.8,93.64 60.11,93.94 65.94,93.94 66.21,93.68 76.42,93.68 76.45,93.64 IC4.28 78.63,93.64 78.85,93.64 79.16,93.94 96.49,93.94 96.8,93.64 IC5.28 | 32.33,93.94 22.96,93.94 22.16,94.74 16.26,94.74 16.26,97.26 IC1.4 | v34.24,67.31 34.47,67.31 34.81,66.97 IC8.5 | v32.33,93.64 32.33,93.94
  Bottom 0.178: v34.24,67.31 32.33,69.22 v32.33,93.64
DA2  (via drill 0.38)
  Top 0.178: IC5.3 84,95.62 79.04,95.62 78.74,95.31 66.4,95.31 66.05,95.66 65.82,95.66 IC4.3 63.65,95.66 60.03,95.66 59.69,95.31 57.29,95.31 56.98,95.62 46.81,95.62 46.77,95.66 IC3.3 44.6,96.15 40.98,96.15 40.6,96.53 31.57,96.53 31.31,96.8 30.77,96.8 28.91,94.93 28.87,94.93 v28.71,94.59 27.69,95.62 IC2.3 25.59,96.19 16.75,96.19 16.75,97.26 IC1.3 | v31.04,67.65 32.87,67.65 34.81,65.71 IC8.6
  Bottom 0.178: v31.04,67.65 30.89,67.81 30.89,92.42 v28.71,94.59
DA3  (via drill 0.38)
  Top 0.178: IC5.31 96.8,97.45 96.49,97.75 78.93,97.75 78.63,97.45 IC4.31 76.45,97.45 76.34,97.56 v75.88,97.56 | 31.69,97.18 30.62,97.18 30.05,96.61 17.28,96.61 17.28,97.26 IC1.2 | 31.69,97.18 IC2.31 40.53,96.91 40.75,96.91 41.14,96.53 46.81,96.53 47.46,97.18 IC3.31 59.58,97.22 v62.97,97.22 | v34.24,62.47 34.81,61.9 IC8.9 | v31.69,97.45 31.69,97.18
  Bottom 0.178: v34.24,62.47 31.69,65.02 v31.69,97.45 | v75.88,97.56 62.97,97.56 v62.97,97.22
DA4  (via drill 0.38)
  Top 0.178: IC1.1 17.82,97.26 25.55,97.26 IC2.2 27.72,97.45 v28.52,97.45 | v44.3,62.47 44.87,61.9 IC8.12 | v43.31,97.18 IC3.2 46.77,97.45 46.89,97.56 47.57,97.56 47.76,97.75 59.61,97.75 59.73,97.87 63.23,97.87 63.65,97.45 IC4.2 65.82,96.91 75.73,96.91 76.04,96.61 78.78,96.61 79.04,96.88 83.96,96.88 84,96.91 IC5.2
  Route2 0.178: v28.52,97.45 30.77,97.45 31.42,96.8 42.74,96.8 42.96,97.03 v43.31,97.18
  Bottom 0.178: v44.3,62.47 43.65,63.12 43.65,78.78 43.31,79.12 v43.31,97.18
DA5  (via drill 0.38)
  Top 0.178: IC5.30 96.8,96.19 96.49,96.49 79.2,96.49 78.89,96.19 78.63,96.19 IC4.30 76.45,96.15 75.96,96.15 75.62,96.49 59.88,96.49 59.58,96.19 IC3.30 57.4,96.15 57.02,96.53 v56.07,96.53 | v32.98,78.09 17.82,78.09 IC1.48 | v37.9,95.31 38.24,95.66 38.35,95.66 IC2.30 | v40.3,67.27 43.31,67.27 44.87,65.71 IC8.15
  Bottom 0.178: 33.31,78.42 36.18,81.29 36.18,93.6 v37.9,95.31 37.74,95.66 35.92,97.49 35.92,99.81 52.79,99.81 v56.07,96.53 | v32.98,78.09 33.31,78.42 | v40.3,67.27 38.05,69.52 38.05,73.67 33.36,78.36 33.31,78.42
DA6  (via drill 0.38)
  Top 0.178: 42.35,99.73 43.57,99.73 44.6,98.7 IC3.1 46.77,98.7 47.12,99.05 63.31,99.05 63.65,98.7 IC4.1 65.82,98.7 66.24,99.12 83.62,99.12 84,98.74 IC5.1 | 38.05,99.73 42.35,99.73 | 38.05,99.73 36.3,99.73 35.76,99.2 29.97,99.2 29.13,100.04 9.78,100.04 9.78,98.82 IC1.17 | v43,67.92 43.92,67.92 44.87,66.97 IC8.16 | 42.35,99.73 v42.35,99.16 | IC2.1 27.72,98.44 36.83,98.44 38.05,99.66 38.05,99.73
  Bottom 0.178: v43,67.92 42.51,68.41 42.51,96.76 42.35,96.91 v42.35,99.16
DISK_CE_L  (via drill 0.38)
  Top 0.178: IC14.5 62.13,28.49 62.13,29.17 IC14.6 64.26,29.51 v72.68,29.51 | v76.95,72.68 76.84,72.57 24.75,72.57 21.97,69.79 IC10.1 | v77.1,71.39 78.85,71.39 IC6.4 78.85,71.08 78.85,70.43 IC6.5 | v76.91,51.04 76.8,51.04 74.36,48.6 SBC.16
  Bottom 0.178: v76.95,72.68 77.1,72.53 v77.1,71.39 76.95,71.04 76.95,51.08 v76.91,51.04 | v72.68,29.51 72.68,46.93 73.37,47.61 SBC.16
DX4  (via drill 0.38)
  Top 0.178: v61.86,60.83 62.43,60.26 IC9.11 | IC5.21 96.8,84.49 86.86,84.49 86.28,85.06 79.2,85.06 78.89,84.76 78.63,84.76 IC4.21 76.45,84.72 76.38,84.8 66.21,84.8 65.94,85.06 63.04,85.06 62.55,84.57 59.58,84.57 IC3.21 57.4,84.53 v56.83,84.53 56.49,84.68 56.11,85.06 40.83,85.06 40.53,84.76 IC2.21 38.35,84.46 37.63,84.46 37.48,84.61 37.06,84.61 36.53,85.14 20.37,85.14 v19.72,84.49 | v15.42,80.19 15.65,80.19 15.65,79.62 IC1.44 | v17.17,43.12 20.45,39.84 24.49,39.84 CF1.6
  Bottom 0.178: v61.86,60.83 61.02,61.67 61.02,64.95 56.83,69.14 v56.83,84.53 | v19.72,84.49 v15.42,80.19 15.57,79.85 17.06,78.36 17.06,43.23 v17.17,43.12
DX5  (via drill 0.38)
  Top 0.178: v69.6,66.62 69.52,66.62 64.41,61.52 IC9.12 | IC5.20 96.8,83.5 96.49,83.81 79.2,83.81 78.85,83.46 78.63,83.46 IC4.20 76.45,83.2 v72.03,83.2 71.69,83.35 66.4,83.35 65.94,83.81 60.72,83.81 60.41,83.5 59.61,83.5 59.58,83.46 IC3.20 57.4,83.46 57.37,83.5 47.19,83.5 46.89,83.81 41.1,83.81 40.75,83.46 40.53,83.46 IC2.20 38.35,83.46 37.55,83.46 37.17,83.85 14.35,83.85 v14.08,84.11 | 14.66,77.44 14.66,78.05 IC1.42 | 14.66,77.44 v14.2,77.44 | v16.41,44.79 20.1,41.1 24.49,41.1 CF1.5 | v16.03,77.44 14.66,77.44
  Bottom 0.178: v69.6,66.62 72.03,69.06 v72.03,83.2 | v14.2,77.44 13.13,78.51 13.13,83.16 v14.08,84.11 | v16.41,44.79 16.03,45.17 v16.03,77.44
DX6  (via drill 0.38)
  Top 0.178: v61.86,63.35 62.43,62.78 IC9.13 | v100.53,71.84 101.1,71.84 IC7.13 | v99.58,81.03 98.93,81.67 IC5.19 96.8,82.21 96.49,82.51 79.16,82.51 78.82,82.17 78.63,82.17 IC4.19 76.45,82.17 66.28,82.17 65.94,82.51 62.32,82.51 61.98,82.17 v61.63,82.02 59.58,82.02 IC3.19 57.4,82.21 57.37,82.25 47.16,82.25 46.89,82.51 41.06,82.51 40.75,82.21 40.53,82.21 IC2.19 38.35,82.21 37.74,82.21 37.4,82.55 v20.56,82.55 v13.82,82.55 | v13.78,80.19 13.78,79.62 IC1.40 | v23.3,43.42 24.33,42.39 24.49,42.39 CF1.4
  Bottom 0.178: v61.86,63.35 62.51,64 62.51,78.97 61.63,79.85 v61.63,82.02 | v100.53,71.84 100.72,72.03 100.72,79.88 v99.58,81.03 | v13.78,80.19 13.82,80.23 v13.82,82.55 | v23.3,43.42 20.56,46.16 v20.56,82.55
DX7  (via drill 0.38)
  Top 0.178: v61.86,64.64 62.43,64.07 IC9.14 | v100.53,69.1 101.1,69.1 IC7.11 | v101.37,78.74 99.73,80.38 98.93,80.38 IC5.18 96.8,80.95 96.49,81.25 79.2,81.25 78.89,80.95 78.63,80.95 IC4.18 76.45,80.91 76.38,80.99 67.04,80.99 66.78,81.25 63.27,81.25 62.89,80.87 60.49,80.87 v60.15,80.72 59.58,80.72 IC3.18 57.4,80.91 57.33,80.99 47.16,80.99 46.89,81.25 41.1,81.25 40.79,80.95 40.53,80.95 IC2.18 38.35,80.91 37.97,80.91 37.63,81.25 30.24,81.25 | 30.24,81.25 24.49,81.25 24.22,81.52 12.75,81.52 12.75,79.62 IC1.38 | v28.3,44.75 27.19,43.65 26.43,43.65 CF1.3 | v30.24,80.72 30.24,81.25
  Bottom 0.178: v61.86,64.64 59.35,67.16 59.35,79.92 v60.15,80.72 | v100.53,69.1 101.37,69.94 v101.37,78.74 | v28.3,44.75 30.24,46.7 v30.24,80.72
DX8  (via drill 0.38)
  Top 0.178: v61.86,65.9 62.43,65.33 IC9.15 | v100.53,66.47 101.1,66.47 IC7.9 | v100.08,78.74 99.7,79.12 98.93,79.12 IC5.17 96.8,79.24 86.7,79.24 86.21,78.74 79.01,78.74 78.63,79.12 IC4.17 76.45,79.16 76.3,79.01 66.13,79.01 65.86,78.74 60.34,78.74 v59.99,78.7 59.58,79.12 IC3.17 57.4,79.16 56.98,78.74 40.91,78.74 40.53,79.12 IC2.17 38.35,79.16 37.94,78.74 19.27,78.74 v18.47,79.54 | v11.84,80.19 11.26,80.19 11.26,79.62 IC1.35 | v20.83,44.79 24.49,44.79 CF1.2
  Route2 0.178: v11.84,80.19 12.87,80.19 13.51,79.54 v18.47,79.54
  Bottom 0.178: v61.86,65.9 59.99,67.77 v59.99,78.7 | v100.53,66.47 99.89,67.12 99.89,78.55 v100.08,78.74 | v20.83,44.79 19.99,45.63 19.99,77.83 18.62,79.2 v18.47,79.54
DX9  (via drill 0.38)
  Top 0.178: v66.51,66.62 64.45,66.62 64.41,66.59 IC9.16 | v96.69,67.92 96.08,67.92 IC7.7 | v90.55,79.88 90.06,80.38 86.13,80.38 IC5.15 84,80.38 83.69,80.07 67.23,80.07 66.85,80.45 v66.51,80.61 65.82,80.61 IC4.15 63.65,80.42 63.31,80.07 47.12,80.07 46.77,80.42 IC3.15 44.6,80.42 44.26,80.07 28.07,80.07 27.72,80.42 IC2.15 25.55,80.61 v24.98,80.61 | v24.75,81.9 10.27,81.9 10.27,79.62 IC1.33 | v27,18.24 26.43,18.24 CF1.23
  Bottom 0.178: v66.51,80.61 v66.51,66.62 | v96.69,67.92 94.28,70.32 94.28,76.15 v90.55,79.88 | v24.75,81.9 24.98,81.67 v24.98,80.61 25.13,80.26 27,78.4 27,51.8 26.39,51.19 26.39,18.85 v27,18.24
DX10  (via drill 0.38)
  Top 0.178: v64.91,69.44 64.83,69.44 64.83,68.3 64.41,67.88 IC9.17 64.41,67.27 73.94,67.27 75.54,65.67 v90.21,65.67 | IC5.14 84,81.67 83.96,81.64 79.04,81.64 78.78,81.37 67.2,81.37 66.89,81.67 65.82,81.67 IC4.14 63.65,81.86 v62.97,81.86 62.62,81.71 62.28,81.37 57.29,81.37 57.02,81.64 46.81,81.64 46.77,81.67 IC3.14 44.6,81.67 44.56,81.64 40.94,81.64 40.68,81.37 38.05,81.37 37.67,81.75 28.68,81.75 v28.33,81.9 27.72,81.9 IC2.14 | v91.35,70.43 93.9,70.43 IC7.5 | v11.07,77.44 9.28,77.44 9.28,78.05 IC1.31 | v23.88,19.53 24.49,19.53 CF1.22
  Route2 0.178: v11.07,77.44 11.26,77.44 12.56,78.74 25.17,78.74 v28.33,81.9
  Bottom 0.178: v64.91,69.44 63.65,70.7 63.65,81.18 v62.97,81.86 | v91.35,70.43 90.21,69.29 v90.21,65.67 | v23.88,19.53 15.15,28.26 15.15,71.62 11.23,75.54 11.23,77.1 v11.07,77.44
DX11  (via drill 0.38)
  Top 0.178: v61.86,68.95 62.43,68.95 IC9.18 | v88.07,73.1 93.9,73.1 IC7.3 | v86.74,83.16 86.13,83.16 IC5.13 84,82.93 83.96,82.89 79.01,82.89 78.66,82.55 66.43,82.55 66.05,82.93 65.82,82.93 IC4.13 63.65,83.16 v60.99,83.16 60.64,83.01 60.26,82.63 57.29,82.63 57.02,82.89 46.81,82.89 46.77,82.93 IC3.13 44.6,82.97 44.53,82.89 40.91,82.89 40.64,82.63 37.86,82.63 37.55,82.93 27.72,82.93 IC2.13 25.55,83.46 14.77,83.46 | 14.77,83.46 8.26,83.46 8.26,79.62 IC1.29 | v23.88,20.79 24.49,20.79 CF1.21 | v14.77,83.2 14.77,83.46
  Bottom 0.178: v61.86,68.95 60.99,69.82 v60.99,83.16 | v88.07,73.1 88.34,73.37 88.34,81.56 v86.74,83.16 | v23.88,20.79 15.53,29.13 15.53,77.03 14.77,77.79 v14.77,83.2
EMA0  (via drill 0.38)
  Top 0.178: v76,73.33 77.22,73.33 77.67,72.87 78.85,72.87 IC6.3 | v73.83,24.14 73.56,23.88 72.53,23.88 71.84,23.19 SBC.35
  Bottom 0.178: v76,73.33 75.27,72.61 75.27,46.96 75.5,46.74 75.5,25.82 v73.83,24.14
EMA1  (via drill 0.38)
  Top 0.178: v78.24,73.52 78.74,73.52 78.85,73.63 IC6.2 | v77.56,47.04 74.7,44.18 73.25,44.18 72.15,43.08 72.15,41.97 v70.59,41.97
  Bottom 0.178: v78.24,73.52 77.75,73.03 77.75,66.78 77.56,66.59 v77.56,47.04 | v70.59,41.97 70.17,41.55 70.17,16.64 70.85,15.95 SBC.41
EMA2  (via drill 0.38)
  Top 0.178: v74.85,73.22 75.81,74.17 78.13,74.17 78.85,74.89 IC6.1
  Route2 0.178: v74.85,73.22 74.85,48.03 73.56,46.74 73.25,46.74 72.15,45.63 72.15,42.09 71.42,41.36 SBC.21
FLASH_L  (via drill 0.38)
  Top 0.178: v73.33,78.36 60.57,78.36 59.65,77.44 27.8,77.44 27.11,76.76 6.77,76.76 6.77,78.05 IC1.26 | v81.33,74.59 82.93,72.99 84.99,72.99 IC6.14
  Bottom 0.178: v73.33,78.36 76.42,75.27 81.33,75.27 v81.33,74.59
FLASH_RDY  (via drill 0.38)
  Top 0.178: v10.73,99.39 10.73,98.82 IC1.15 | v96.69,69.06 96.08,69.06 IC7.6
  Bottom 0.178: v10.73,99.39 11.84,100.5 96.04,100.5 96.04,69.71 v96.69,69.06
FPGA_DONE_H  (via drill 0.38)
  Top 0.178: v111.66,57.06 110.48,57.06 IC12.72 | v96.69,73.71 96.49,73.9 96.08,73.9 IC7.2
  Route2 0.178: v111.66,57.06 111.66,58.81 101.18,69.29 101.18,69.37 96.84,73.71 v96.69,73.71
FPGA_INIT_L/RTC_CLK  (via drill 0.38)
  Top 0.178: v93.03,71.62 93.9,71.62 IC7.4 96.08,71.92 99.16,71.92 100.72,73.48 103.39,73.48 107.12,69.75 v107.12,68.15 | v92.8,69.14 91.39,69.14 R3.2 | IC12.68 110.48,55.12 111.77,55.12 113.64,56.98 J3.1 | v117.72,20.56 121.91,20.56 122.29,20.18 IC16.7
  Route2 0.178: v107.12,68.15 114.06,61.21 114.06,59.12 115.2,57.98 J3.1
  Bottom 0.178: v93.03,71.62 92.8,71.39 v92.8,69.14 | v117.72,20.56 116.42,21.86 116.42,56.95 J3.1
FPGA_L  (via drill 0.38)
  Top 0.178: v99.96,42.77 101.45,41.29 105.26,41.29 105.26,38.47 IC12.31 | v88,66.97 87.69,67.27 86.97,67.27 IC6.10
  Route2 0.178: v94.59,53.71 91.43,56.87 89.94,56.87 v88.49,58.32
  Bottom 0.178: v99.96,42.77 98.93,43.8 97.83,43.8 97.83,50.47 v94.59,53.71 | v88.49,58.32 88,58.81 v88,66.97
FPGA_PROGRAM_L  (via drill 0.38)
  Top 0.178: v104,53.71 105.6,53.71 107.35,55.46 108.92,55.46 IC12.69 | v101.26,57.48 101.87,58.09 IC12.85 | v101.03,63.58 100.19,63.58 R2.2
  Route2 0.178: v104,53.71 103.77,53.71 103.09,53.02 100.34,53.02 99.92,53.44 99.92,56.15 v101.26,57.48
  Bottom 0.178: v101.03,63.58 100.88,63.42 100.88,58.05 101.1,57.82 v101.26,57.48
FPGA_WR_L/RTC_IO  (via drill 0.38)
  Top 0.178: v103.73,39.19 104.76,39.19 104.76,38.47 IC12.30 | v107.09,35.84 107.16,35.92 111.01,35.92 R7.2 112.57,35.92 113.56,34.93 121.98,34.93 v122.36,34.54 | v123.24,17.59 123.58,17.59 123.58,18.05 IC16.6
  Bottom 0.178: v107.09,35.84 v103.73,39.19 | v123.24,17.59 122.36,18.47 v122.36,34.54
G0  (via drill 0.38)
  Top 0.178: v82.32,49.02 82.97,48.37 87.39,48.37 87.5,48.49 87.69,48.49 IC12.126 | v132.96,71.31 134.29,69.98 136.39,69.98 137.68,68.68 139.85,68.68 140.23,68.3 R12.1
  Route2 0.178: v82.32,49.02 82.32,55.04 81.67,55.69 81.67,65.71 91.54,75.58 119.35,75.58 123.47,71.46 132.8,71.46 v132.96,71.31
GND  (via drill 0.38)
  Top 0.254: 23.69,28.91 23.65,28.87 23.65,28.3 23.69,28.26 24.49,28.26 CF1.15 | 23.69,28.91 CF1.39 | 23.69,28.91 23.65,29.02 23.65,29.51 23.69,29.55 24.49,29.55 CF1.14 26.43,29.55 v27.04,29.55 | IC1.47 17.21,78.05 17.21,77.25 17.17,77.22 16.75,77.22 16.71,77.25 16.71,78.05 IC1.46 16.71,79.62 v16.71,80.23 | v7.19,80.23 7.19,79.62 IC1.27 | v23.84,14.92 24.49,14.92 CF1.50 | v23.84,25.74 24.49,25.74 CF1.17 | v23.84,27 CF1.16 | v23.84,32.07 24.49,32.07 CF1.12 | v23.84,33.36 24.49,33.36 CF1.11 | v23.84,34.62 CF1.10 | v23.84,37.17 24.49,37.17 CF1.8 | v23.84,46.05 CF1.1 | v19.34,61.86 19.99,61.86 IC10.7 | v34.16,60.34 34.81,60.34 IC8.10 | v34.16,71.77 34.81,71.77 IC8.1 | v51.73,59.96 52.37,59.96 IC9.10 | v61.79,70.09 62.43,70.09 IC9.19 | IC17.7 v129.95,7.65 | v78.21,66.32 IC6.8 | v129.95,17.82 130.59,17.82 IC15.7 | v136.08,14.01 136.73,14.01 IC17.13 | v129.95,20.33 130.59,20.33 IC15.5 | v136.08,19.08 IC15.9 | v136.08,21.63 136.73,21.63 IC15.11 | v126.71,32.41 IC13.10 | v136.08,24.14 136.73,24.14 IC15.13 | v119.58,60.11 120.23,60.11 IC11.8 | v136.77,42.58 137.41,42.58 IC13.19 | v9.32,72.3 9.32,72.95 C8.2 | v56.26,28.18 56.91,28.18 IC14.4 | v56.26,29.48 56.91,29.48 IC14.3 | v61.67,34.39 61.67,35.04 C17.2 | v29.55,71.35 30.2,71.35 C13.2 | v24.9,79.39 25.55,79.39 IC2.16 | v28.37,74.85 28.37,75.5 C5.2 | v48.18,66.93 48.83,66.93 C14.2 | v43.95,79.39 44.6,79.39 IC3.16 | v125.11,15.61 125.11,15 IC16.4 | v65.63,74.85 65.63,75.5 C6.2 | v63,79.39 63.65,79.39 IC4.16 | v93.26,66.55 IC7.8 | v83.35,79.39 84,79.39 IC5.16 | v91.35,73.75 91.35,74.4 C9.2 | v108.84,76.76 108.84,77.41 C7.2 | v101.1,84.49 101.75,84.49 REG2.5.2 | v101.1,85.75 REG2.5.1 | v104.91,89.75 104.91,89.14 C3.2
  Top 0.254: v109.98,84.49 110.63,84.49 REG3.3.2 | v109.98,85.75 REG3.3.1 113.64,85.75 113.72,85.83 113.72,87.43 C4.2 | v132.99,67.31 133.64,67.31 C10.2 | v114.13,67.04 114.13,67.69 X1.P$2 | v133.11,63.31 133.76,63.31 C11.2 | v18.47,57.33 18.47,57.98 R4.2 | v105.45,96.46 105.45,97.1 C1.- | v114.33,96.46 C2.- | IC12.110 87.73,56.68 87.73,56.91 IC12.109 87.69,57.02 v87.12,57.02 | v87.12,40.03 87.69,40.03 IC12.143 | v93.83,39.04 93.83,38.47 IC12.8 | v87.12,44.03 87.69,44.03 IC12.135 | v89.87,47.54 89.26,47.54 IC12.128 | v98.32,39.04 98.32,38.47 IC12.17 | v87.12,52.03 87.69,52.03 IC12.119 | v102.32,39.04 102.32,38.47 IC12.25 | v106.32,39.04 106.32,38.47 IC12.33 | v91.35,57.52 91.35,58.09 IC12.106 | v95.35,57.52 95.35,58.09 IC12.98 | v108.31,43.54 108.92,43.54 IC12.45 | v108.31,47.04 108.92,47.04 IC12.52 | v99.85,57.52 99.85,58.09 IC12.89 | v103.85,57.52 103.85,58.09 IC12.81 | v108.31,51.54 108.92,51.54 IC12.61 | v107.85,60.26 107.85,59.65 IC12.73 | v110.44,34.62 111.01,34.62 R7.1
  Bottom 0.254: C106.2 113.91,49.59 113.91,48.83 113.87,48.79 113.87,47.96 C102.2 113.87,46.47 v113.87,45.9 | C103.2 84.38,49.75 84.38,48.68 C104.2 84.38,47.19 v84.38,46.62 | C107.2 98.97,63.12 98.55,63.12 98.51,63.16 98.02,63.16 C105.2 96.53,63.16 v95.96,63.16 | v95.54,33.48 96.15,33.48 C101.2 97.6,33.48 98.55,33.48 C100.2
HS  (via drill 0.38)
  Top 0.178: v104.08,47.65 94.93,47.65 89.6,52.98 89.26,52.98 IC12.117 | v125.11,72.99 126.67,74.55 136.8,74.55 148.88,86.63 148.88,89.67 149.19,89.67 VGA.13
  Route2 0.178: v104.08,47.65 106.4,47.65 107.12,48.37 111.43,48.37 111.89,47.92 115.35,47.92 v118.21,50.77
  Bottom 0.178: v118.21,50.77 120.54,53.1 120.54,59.61 124.57,63.65 124.57,64.83 124.46,64.95 124.46,72.34 v125.11,72.99
INTGNT_L  (via drill 0.38)
  Top 0.178: v84.42,41.06 87.69,41.06 IC12.141
  Route2 0.178: v84.42,41.06 80.26,41.06 v74.85,46.47
  Bottom 0.178: v74.85,46.47 74.66,46.66 74.66,54.58 74.02,55.23 SBC.10
INTREQ_L
  Top 0.178: IC12.96 96.27,58.09 96.27,56.87 89.94,56.87 89.56,57.25 89.56,57.67 74.85,57.67 74.09,56.91 72.57,56.91 71.84,56.18 SBC.9
IOCLR_L  (via drill 0.38)
  Top 0.178: v102.44,60.95 100.88,60.95 100.88,59.65 IC12.87 | v87.12,53.4 74.36,53.4 SBC.12 72.99,53.67 72.3,54.36 v29.59,54.36 | v13.28,95.92 12.26,96.95 12.26,97.26 IC1.12 | v27.69,28.6 26.73,27.65 26.73,26.51 26.43,26.51 CF1.41
  Route2 0.178: v102.44,60.95 97.71,60.95 96.38,59.61 94.7,59.61 v92.76,61.56
  Bottom 0.178: v92.76,61.56 90.28,59.08 90.28,58.51 87.12,55.35 v87.12,53.4 | v13.28,95.92 18.81,90.4 18.81,88.76 27.65,79.92 27.65,54.36 | 27.65,54.36 27.65,29.86 27.69,29.82 v27.69,28.6 | 27.65,54.36 v29.59,54.36
KB_CLK  (via drill 0.38)
  Top 0.178: v90.17,42.77 89.98,42.58 89.26,42.58 IC12.138 | v95.69,48.3 98.86,51.46 v104.46,51.46 | v123.43,72.61 123.7,72.34 144.2,72.34 146.79,69.75 KBD.6
  Route2 0.178: v90.17,42.77 v95.69,48.3 | v104.46,51.46 v110.71,57.71
  Bottom 0.178: v110.71,57.71 111.43,58.43 118.94,58.43 118.94,62.05 123.43,66.55 v123.43,72.61
KB_DATA  (via drill 0.38)
  Top 0.178: v80.91,43.8 82.17,45.06 87.69,45.06 IC12.133
  Route2 0.178: v84.34,64.22 88.34,68.22 88.99,68.22 90.7,69.94 90.7,70.7 95.01,75.01 116.99,75.01 125.37,66.62 148.84,66.62 149.26,67.04 KBD.1
  Bottom 0.178: v80.91,43.8 80.91,50.7 81.18,50.97 81.18,61.06 v84.34,64.22
LOAD_DAR_H  (via drill 0.38)
  Top 0.178: v55.46,55.5 51.38,55.5 46.85,60.03 IC8.11 | v58.24,52.72 62.36,48.6 70.47,48.6 SBC.15
  Bottom 0.178: v55.46,55.5 v58.24,52.72
LXDAR_L  (via drill 0.38)
  Top 0.178: v92.19,41.14 93.75,41.14 95.12,39.76 98.97,39.76 98.97,38.77 98.9,38.7 98.9,38.47 IC12.18 | v85.98,52.34 85.33,51.69 74.89,51.69 74.36,51.16 SBC.14
  Route2 0.178: v92.11,55.27 91.24,55.27 90.09,54.13 88.76,54.13 87.31,52.68 86.32,52.68 v85.98,52.34
  Bottom 0.178: v92.19,41.14 91.85,41.48 91.85,55 v92.11,55.27
MA0  (via drill 0.38)
  Top 0.178: v15.27,96.65 15.27,97.26 IC1.6 | v19.46,90.47 19.8,90.13 37.82,90.13 38.13,89.83 38.35,89.83 IC2.25 40.53,89.83 40.56,89.87 44.22,89.87 44.49,90.13 53.56,90.13 53.9,89.79 57.4,89.79 IC3.25 59.58,89.83 59.61,89.87 63.27,89.87 63.54,90.13 66.4,90.13 | 66.4,90.13 67.46,90.13 67.77,89.83 76.45,89.83 IC4.25 78.63,89.83 78.85,89.83 79.16,90.13 96.49,90.13 96.8,89.83 IC5.25 | v66.89,32.07 71.73,32.07 72.99,30.81 SBC.30 | v66.4,89.87 66.4,90.13
  Bottom 0.178: v15.27,96.65 16.64,95.28 16.64,93.29 v19.46,90.47 | v66.89,32.07 66.51,32.45 66.51,55.5 65.86,56.15 65.86,67.73 66.13,68 66.13,73.44 64.99,74.59 64.99,88.46 v66.4,89.87
MA1  (via drill 0.38)
  Top 0.178: v14.77,99.39 14.77,98.82 IC1.7 | v23.19,87.66 23.23,87.62 37.78,87.62 38.13,87.27 38.35,87.27 IC2.23 40.53,87.27 40.75,87.27 41.1,87.62 46.89,87.62 47.19,87.31 53.52,87.31 | 53.52,87.31 57.37,87.31 57.4,87.27 IC3.23 59.58,87.27 59.8,87.27 60.15,87.62 65.94,87.62 66.55,87.01 76.45,87.01 IC4.23 78.63,87.27 78.85,87.27 79.2,87.62 96.49,87.62 96.8,87.31 IC5.23 | v56.3,30.66 56.79,30.16 59.35,30.16 59.35,29.51 61.9,26.96 72.26,26.96 72.99,27.69 SBC.32 | v53.52,87.08 53.52,87.31
  Bottom 0.178: v14.77,99.39 17.02,97.14 17.02,93.83 v23.19,87.66 | v56.3,30.66 53.52,33.44 v53.52,87.08
MA2  (via drill 0.38)
  Top 0.178: v17.67,94.09 14.27,94.09 14.27,97.26 IC1.8 | v28.18,91.47 28.56,91.08 38.35,91.08 IC2.26 40.53,91.08 44.15,91.08 44.49,91.43 46.89,91.43 47.19,91.12 56.07,91.12 | 56.07,91.12 57.37,91.12 57.4,91.08 IC3.26 59.58,91.08 63.2,91.08 63.54,91.43 65.94,91.43 66.47,90.89 76.45,90.89 IC4.26 78.63,91.08 79.39,91.08 79.73,91.43 96.49,91.43 96.8,91.12 IC5.26 | v64.57,40.11 70.09,34.58 71.73,34.58 72.99,33.32 SBC.28 | v56.07,90.89 56.07,91.12
  Bottom 0.178: v17.67,94.09 20.29,91.47 v28.18,91.47 | v64.57,40.11 60.64,44.03 60.64,64.8 56.11,69.33 56.11,84.53 56.07,84.57 v56.07,90.89
MA3  (via drill 0.38)
  Top 0.178: v30.24,99.85 29.59,100.5 9.28,100.5 9.28,98.82 IC1.18 | v35.53,92.34 38.35,92.34 IC2.27 40.53,92.38 40.56,92.42 44.22,92.42 44.49,92.68 56.15,92.68 v56.41,92.46 56.53,92.34 57.4,92.34 IC3.27 59.58,92.38 59.61,92.42 63.27,92.42 63.54,92.68 75.43,92.68 75.77,92.34 76.45,92.34 IC4.27 78.63,92.11 79.35,92.11 79.92,92.68 96.49,92.68 96.8,92.38 IC5.27 | v57.33,44.83 61.67,44.83 69.37,37.13 71.01,37.13 71.96,36.18 72.68,36.18 72.99,35.88 SBC.26
  Bottom 0.178: v30.24,99.85 35.53,94.55 v35.53,92.34 | v57.33,44.83 54.81,47.35 54.81,90.86 v56.41,92.46
MA4  (via drill 0.38)
  Top 0.178: IC1.19 8.79,97.26 8.79,93.45 25.55,93.45 IC2.5 27.72,93.1 27.84,92.99 38.05,92.99 38.24,92.8 44.07,92.8 44.37,93.1 44.6,93.1 IC3.5 46.77,93.1 56.98,93.1 57.29,92.8 63.12,92.8 63.42,93.1 63.65,93.1 IC4.5 65.82,93.1 75.54,93.1 75.84,92.8 78.78,92.8 78.91,92.93 | 78.91,92.93 79.04,93.07 83.96,93.07 84,93.1 IC5.5 | v72.8,49.17 72.68,49.17 72.68,48.41 71.58,47.31 69.56,47.31 69.56,40.11 70.85,38.81 SBC.23 | v79.08,92.76 78.97,92.88 78.91,92.93
  Bottom 0.178: v72.8,49.17 72.68,49.29 72.68,86.36 v79.08,92.76
MA5  (via drill 0.38)
  Top 0.178: IC1.20 8.26,97.26 8.26,92.38 25.59,92.38 IC2.6 27.72,92.11 34.85,92.11 35.46,91.5 44.03,91.5 44.37,91.85 44.6,91.85 IC3.6 46.77,91.85 46.81,91.81 56.98,91.81 57.29,91.5 63.08,91.5 63.42,91.85 63.65,91.85 IC4.6 65.82,91.85 66.05,91.85 66.4,91.5 68.41,91.5 | 68.41,91.5 79.27,91.5 79.58,91.81 84,91.81 IC5.6 | v68.83,36.75 69.63,36.75 70.47,35.92 SBC.25 | 68.41,91.5 v68.41,91.54
  Bottom 0.178: v68.83,36.75 68.41,37.17 v68.41,91.54
MA6  (via drill 0.38)
  Top 0.178: IC1.21 7.76,97.26 7.76,91.12 25.59,91.12 IC2.7 27.72,90.55 27.76,90.51 37.97,90.51 38.24,90.25 44.07,90.25 44.41,90.59 44.6,90.59 IC3.7 46.77,90.55 46.81,90.51 54.17,90.51 | 54.17,90.51 55.23,90.51 55.5,90.25 62.51,90.25 62.85,90.59 63.65,90.59 IC4.7 65.82,90.55 65.86,90.51 67.61,90.51 67.88,90.25 78.74,90.25 79.01,90.51 83.96,90.51 84,90.55 IC5.7 | v57.33,35.69 59.65,33.36 70.47,33.36 SBC.27 | v54.17,90.44 54.17,90.51
  Bottom 0.178: v57.33,35.69 54.17,38.85 v54.17,90.44
MA7  (via drill 0.38)
  Top 0.178: IC1.22 7.26,97.26 7.26,89.75 25.55,89.75 IC2.8 27.72,89.33 27.91,89.33 28.26,88.99 40.68,88.99 40.94,89.26 44.56,89.26 44.6,89.29 IC3.8 46.77,89.29 56.41,89.29 56.72,88.99 59.73,88.99 59.99,89.26 63.61,89.26 63.65,89.29 IC4.8 65.82,89.29 66.05,89.29 66.36,88.99 67.42,88.99 | 67.42,88.99 78.78,88.99 79.04,89.26 83.96,89.26 84,89.29 IC5.8 | v68.83,31.42 69.86,31.42 70.47,30.81 SBC.29 | 67.42,88.99 v67.42,89.26
  Bottom 0.178: v68.83,31.42 67.92,32.33 67.92,88.76 v67.42,89.26
MA8  (via drill 0.38)
  Top 0.178: IC1.23 6.65,97.26 6.65,89.56 6.31,89.22 6.31,88.3 25.55,88.3 IC2.9 27.72,88.04 27.76,88 37.94,88 38.24,87.69 40.64,87.69 40.98,88.04 44.6,88.04 IC3.9 46.77,88.04 46.81,88 56.98,88 57.29,87.69 59.69,87.69 60.03,88.04 63.65,88.04 IC4.9 65.82,88.04 66.05,88.04 66.4,87.69 69.71,87.69 | 69.71,87.69 78.74,87.69 79.04,88 84,88 IC5.9 | 69.71,87.69 v69.71,87.66
  Route2 0.178: v69.71,87.66 69.71,76.99 68.95,76.23 68.95,55.23 69.48,54.7 69.48,30.73 70.82,29.4 70.82,28.64 SBC.31
MA9
  Top 0.178: SBC.33 70.47,25.1 69.98,24.6 26.43,24.6 CF1.18 24.49,24.6 24.07,24.6 3.04,45.63 3.04,86.97 5.78,86.97 5.85,87.01 | 5.85,87.01 5.85,89.37 6.08,89.6 6.08,97.26 IC1.24 | 5.85,87.01 25.55,87.01 IC2.10 27.72,86.74 28.03,86.44 44.26,86.44 44.6,86.78 IC3.10 46.77,86.74 47.08,86.44 63.31,86.44 63.65,86.78 IC4.10 65.82,86.74 66.13,86.44 78.74,86.44 79.01,86.7 83.96,86.7 84,86.74 IC5.10
MA10  (via drill 0.38)
  Top 0.178: 40.94,23.34 49.4,23.34 50.13,24.07 67.08,24.07 70.47,20.68 SBC.37 | 40.94,23.34 26.43,23.34 CF1.19 | IC1.25 6.27,79.62 6.27,85.52 25.55,85.52 IC2.11 v36.83,85.75 | IC5.11 84,85.48 83.96,85.45 79.04,85.45 78.78,85.18 66.36,85.18 66.05,85.48 65.82,85.48 IC4.11 63.65,85.48 62.93,85.48 62.4,84.95 60.34,84.95 60.22,85.06 57.4,85.06 56.98,85.48 46.77,85.48 IC3.11 v41.1,85.75 | 40.94,23.34 v40.94,23.42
